VERSION 5.7 ;
  NOWIREEXTENSIONATPIN ON ;
  DIVIDERCHAR "/" ;
  BUSBITCHARS "[]" ;
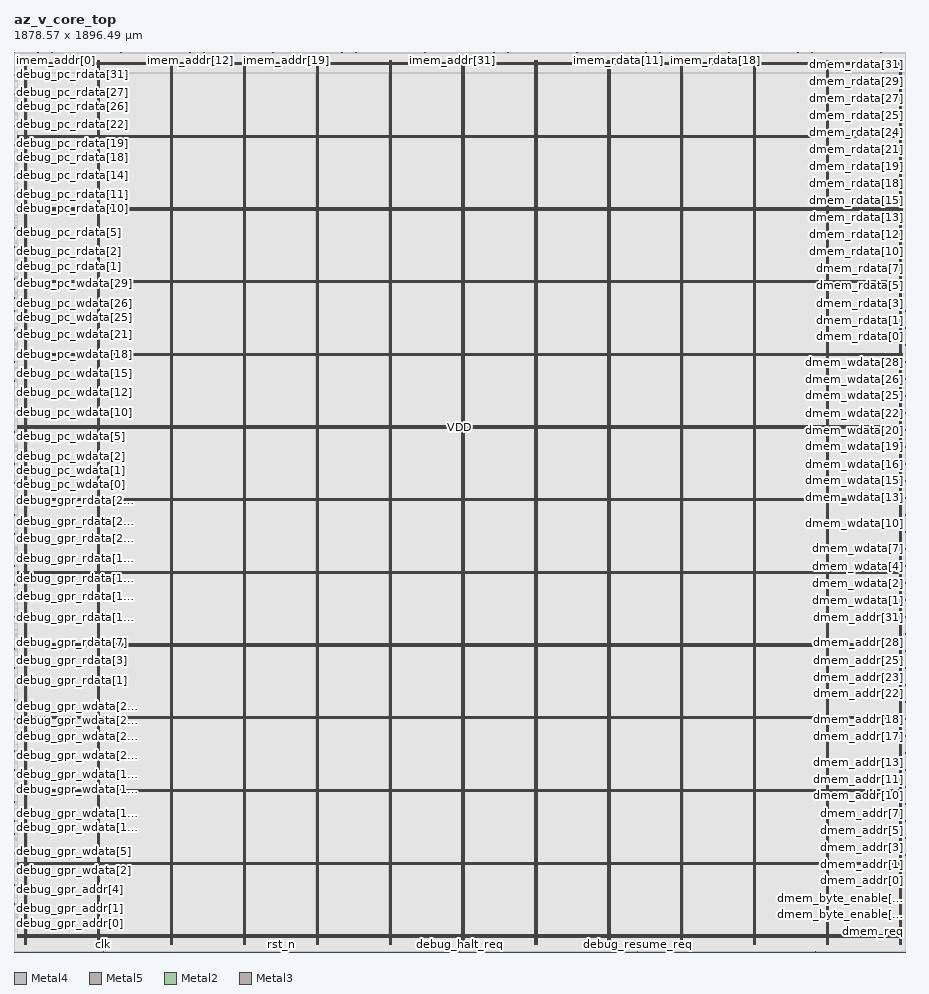
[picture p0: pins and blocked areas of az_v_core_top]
MACRO az_v_core_top
  CLASS BLOCK ;
  FOREIGN az_v_core_top ;
  ORIGIN 0.000 0.000 ;
  SIZE 1878.570 BY 1896.490 ;
  PIN VDD
    DIRECTION INOUT ;
    USE POWER ;
    PORT
      LAYER Metal4 ;
        RECT 22.240 15.380 23.840 1877.980 ;
    END
    PORT
      LAYER Metal4 ;
        RECT 175.840 15.380 177.440 1877.980 ;
    END
    PORT
      LAYER Metal4 ;
        RECT 329.440 15.380 331.040 1877.980 ;
    END
    PORT
      LAYER Metal4 ;
        RECT 483.040 15.380 484.640 1877.980 ;
    END
    PORT
      LAYER Metal4 ;
        RECT 636.640 15.380 638.240 1877.980 ;
    END
    PORT
      LAYER Metal4 ;
        RECT 790.240 15.380 791.840 1877.980 ;
    END
    PORT
      LAYER Metal4 ;
        RECT 943.840 15.380 945.440 1877.980 ;
    END
    PORT
      LAYER Metal4 ;
        RECT 1097.440 15.380 1099.040 1877.980 ;
    END
    PORT
      LAYER Metal4 ;
        RECT 1251.040 15.380 1252.640 1877.980 ;
    END
    PORT
      LAYER Metal4 ;
        RECT 1404.640 15.380 1406.240 1877.980 ;
    END
    PORT
      LAYER Metal4 ;
        RECT 1558.240 15.380 1559.840 1877.980 ;
    END
    PORT
      LAYER Metal4 ;
        RECT 1711.840 15.380 1713.440 1877.980 ;
    END
    PORT
      LAYER Metal4 ;
        RECT 1865.440 15.380 1867.040 1877.980 ;
    END
    PORT
      LAYER Metal5 ;
        RECT 6.720 31.530 1871.520 33.130 ;
    END
    PORT
      LAYER Metal5 ;
        RECT 6.720 184.710 1871.520 186.310 ;
    END
    PORT
      LAYER Metal5 ;
        RECT 6.720 337.890 1871.520 339.490 ;
    END
    PORT
      LAYER Metal5 ;
        RECT 6.720 491.070 1871.520 492.670 ;
    END
    PORT
      LAYER Metal5 ;
        RECT 6.720 644.250 1871.520 645.850 ;
    END
    PORT
      LAYER Metal5 ;
        RECT 6.720 797.430 1871.520 799.030 ;
    END
    PORT
      LAYER Metal5 ;
        RECT 6.720 950.610 1871.520 952.210 ;
    END
    PORT
      LAYER Metal5 ;
        RECT 6.720 1103.790 1871.520 1105.390 ;
    END
    PORT
      LAYER Metal5 ;
        RECT 6.720 1256.970 1871.520 1258.570 ;
    END
    PORT
      LAYER Metal5 ;
        RECT 6.720 1410.150 1871.520 1411.750 ;
    END
    PORT
      LAYER Metal5 ;
        RECT 6.720 1563.330 1871.520 1564.930 ;
    END
    PORT
      LAYER Metal5 ;
        RECT 6.720 1716.510 1871.520 1718.110 ;
    END
    PORT
      LAYER Metal5 ;
        RECT 6.720 1869.690 1871.520 1871.290 ;
    END
  END VDD
  PIN VSS
    DIRECTION INOUT ;
    USE GROUND ;
    PORT
      LAYER Metal4 ;
        RECT 25.540 15.380 27.140 1877.980 ;
    END
    PORT
      LAYER Metal4 ;
        RECT 179.140 15.380 180.740 1877.980 ;
    END
    PORT
      LAYER Metal4 ;
        RECT 332.740 15.380 334.340 1877.980 ;
    END
    PORT
      LAYER Metal4 ;
        RECT 486.340 15.380 487.940 1877.980 ;
    END
    PORT
      LAYER Metal4 ;
        RECT 639.940 15.380 641.540 1877.980 ;
    END
    PORT
      LAYER Metal4 ;
        RECT 793.540 15.380 795.140 1877.980 ;
    END
    PORT
      LAYER Metal4 ;
        RECT 947.140 15.380 948.740 1877.980 ;
    END
    PORT
      LAYER Metal4 ;
        RECT 1100.740 15.380 1102.340 1877.980 ;
    END
    PORT
      LAYER Metal4 ;
        RECT 1254.340 15.380 1255.940 1877.980 ;
    END
    PORT
      LAYER Metal4 ;
        RECT 1407.940 15.380 1409.540 1877.980 ;
    END
    PORT
      LAYER Metal4 ;
        RECT 1561.540 15.380 1563.140 1877.980 ;
    END
    PORT
      LAYER Metal4 ;
        RECT 1715.140 15.380 1716.740 1877.980 ;
    END
    PORT
      LAYER Metal4 ;
        RECT 1868.740 15.380 1870.340 1877.980 ;
    END
    PORT
      LAYER Metal5 ;
        RECT 6.720 34.830 1871.520 36.430 ;
    END
    PORT
      LAYER Metal5 ;
        RECT 6.720 188.010 1871.520 189.610 ;
    END
    PORT
      LAYER Metal5 ;
        RECT 6.720 341.190 1871.520 342.790 ;
    END
    PORT
      LAYER Metal5 ;
        RECT 6.720 494.370 1871.520 495.970 ;
    END
    PORT
      LAYER Metal5 ;
        RECT 6.720 647.550 1871.520 649.150 ;
    END
    PORT
      LAYER Metal5 ;
        RECT 6.720 800.730 1871.520 802.330 ;
    END
    PORT
      LAYER Metal5 ;
        RECT 6.720 953.910 1871.520 955.510 ;
    END
    PORT
      LAYER Metal5 ;
        RECT 6.720 1107.090 1871.520 1108.690 ;
    END
    PORT
      LAYER Metal5 ;
        RECT 6.720 1260.270 1871.520 1261.870 ;
    END
    PORT
      LAYER Metal5 ;
        RECT 6.720 1413.450 1871.520 1415.050 ;
    END
    PORT
      LAYER Metal5 ;
        RECT 6.720 1566.630 1871.520 1568.230 ;
    END
    PORT
      LAYER Metal5 ;
        RECT 6.720 1719.810 1871.520 1721.410 ;
    END
    PORT
      LAYER Metal5 ;
        RECT 6.720 1872.990 1871.520 1874.590 ;
    END
  END VSS
  PIN clk
    DIRECTION INPUT ;
    USE SIGNAL ;
    ANTENNAGATEAREA 4.738000 ;
    PORT
      LAYER Metal2 ;
        RECT 188.160 0.000 188.720 0.560 ;
    END
  END clk
  PIN debug_gpr_addr[0]
    DIRECTION INPUT ;
    USE SIGNAL ;
    ANTENNAGATEAREA 2.204000 ;
    PORT
      LAYER Metal3 ;
        RECT 0.000 60.480 0.560 61.040 ;
    END
  END debug_gpr_addr[0]
  PIN debug_gpr_addr[1]
    DIRECTION INPUT ;
    USE SIGNAL ;
    ANTENNAGATEAREA 2.204000 ;
    PORT
      LAYER Metal3 ;
        RECT 0.000 73.920 0.560 74.480 ;
    END
  END debug_gpr_addr[1]
  PIN debug_gpr_addr[2]
    DIRECTION INPUT ;
    USE SIGNAL ;
    ANTENNAGATEAREA 0.498500 ;
    PORT
      LAYER Metal3 ;
        RECT 0.000 87.360 0.560 87.920 ;
    END
  END debug_gpr_addr[2]
  PIN debug_gpr_addr[3]
    DIRECTION INPUT ;
    USE SIGNAL ;
    ANTENNAGATEAREA 1.102000 ;
    PORT
      LAYER Metal3 ;
        RECT 0.000 100.800 0.560 101.360 ;
    END
  END debug_gpr_addr[3]
  PIN debug_gpr_addr[4]
    DIRECTION INPUT ;
    USE SIGNAL ;
    ANTENNAGATEAREA 1.102000 ;
    PORT
      LAYER Metal3 ;
        RECT 0.000 114.240 0.560 114.800 ;
    END
  END debug_gpr_addr[4]
  PIN debug_gpr_rdata[0]
    DIRECTION OUTPUT ;
    USE SIGNAL ;
    ANTENNADIFFAREA 0.897600 ;
    PORT
      LAYER Metal3 ;
        RECT 0.000 557.760 0.560 558.320 ;
    END
  END debug_gpr_rdata[0]
  PIN debug_gpr_rdata[10]
    DIRECTION OUTPUT ;
    USE SIGNAL ;
    ANTENNADIFFAREA 0.897600 ;
    PORT
      LAYER Metal3 ;
        RECT 0.000 692.160 0.560 692.720 ;
    END
  END debug_gpr_rdata[10]
  PIN debug_gpr_rdata[11]
    DIRECTION OUTPUT ;
    USE SIGNAL ;
    ANTENNADIFFAREA 0.897600 ;
    PORT
      LAYER Metal3 ;
        RECT 0.000 705.600 0.560 706.160 ;
    END
  END debug_gpr_rdata[11]
  PIN debug_gpr_rdata[12]
    DIRECTION OUTPUT ;
    USE SIGNAL ;
    ANTENNADIFFAREA 0.897600 ;
    PORT
      LAYER Metal3 ;
        RECT 0.000 719.040 0.560 719.600 ;
    END
  END debug_gpr_rdata[12]
  PIN debug_gpr_rdata[13]
    DIRECTION OUTPUT ;
    USE SIGNAL ;
    ANTENNADIFFAREA 0.897600 ;
    PORT
      LAYER Metal3 ;
        RECT 0.000 732.480 0.560 733.040 ;
    END
  END debug_gpr_rdata[13]
  PIN debug_gpr_rdata[14]
    DIRECTION OUTPUT ;
    USE SIGNAL ;
    ANTENNADIFFAREA 0.897600 ;
    PORT
      LAYER Metal3 ;
        RECT 0.000 745.920 0.560 746.480 ;
    END
  END debug_gpr_rdata[14]
  PIN debug_gpr_rdata[15]
    DIRECTION OUTPUT ;
    USE SIGNAL ;
    ANTENNADIFFAREA 0.897600 ;
    PORT
      LAYER Metal3 ;
        RECT 0.000 759.360 0.560 759.920 ;
    END
  END debug_gpr_rdata[15]
  PIN debug_gpr_rdata[16]
    DIRECTION OUTPUT ;
    USE SIGNAL ;
    ANTENNADIFFAREA 0.897600 ;
    PORT
      LAYER Metal3 ;
        RECT 0.000 772.800 0.560 773.360 ;
    END
  END debug_gpr_rdata[16]
  PIN debug_gpr_rdata[17]
    DIRECTION OUTPUT ;
    USE SIGNAL ;
    ANTENNADIFFAREA 0.897600 ;
    PORT
      LAYER Metal3 ;
        RECT 0.000 786.240 0.560 786.800 ;
    END
  END debug_gpr_rdata[17]
  PIN debug_gpr_rdata[18]
    DIRECTION OUTPUT ;
    USE SIGNAL ;
    ANTENNADIFFAREA 0.897600 ;
    PORT
      LAYER Metal3 ;
        RECT 0.000 799.680 0.560 800.240 ;
    END
  END debug_gpr_rdata[18]
  PIN debug_gpr_rdata[19]
    DIRECTION OUTPUT ;
    USE SIGNAL ;
    ANTENNADIFFAREA 0.897600 ;
    PORT
      LAYER Metal3 ;
        RECT 0.000 813.120 0.560 813.680 ;
    END
  END debug_gpr_rdata[19]
  PIN debug_gpr_rdata[1]
    DIRECTION OUTPUT ;
    USE SIGNAL ;
    ANTENNADIFFAREA 0.897600 ;
    PORT
      LAYER Metal3 ;
        RECT 0.000 571.200 0.560 571.760 ;
    END
  END debug_gpr_rdata[1]
  PIN debug_gpr_rdata[20]
    DIRECTION OUTPUT ;
    USE SIGNAL ;
    ANTENNADIFFAREA 0.897600 ;
    PORT
      LAYER Metal3 ;
        RECT 0.000 826.560 0.560 827.120 ;
    END
  END debug_gpr_rdata[20]
  PIN debug_gpr_rdata[21]
    DIRECTION OUTPUT ;
    USE SIGNAL ;
    ANTENNADIFFAREA 0.897600 ;
    PORT
      LAYER Metal3 ;
        RECT 0.000 840.000 0.560 840.560 ;
    END
  END debug_gpr_rdata[21]
  PIN debug_gpr_rdata[22]
    DIRECTION OUTPUT ;
    USE SIGNAL ;
    ANTENNADIFFAREA 0.897600 ;
    PORT
      LAYER Metal3 ;
        RECT 0.000 853.440 0.560 854.000 ;
    END
  END debug_gpr_rdata[22]
  PIN debug_gpr_rdata[23]
    DIRECTION OUTPUT ;
    USE SIGNAL ;
    ANTENNADIFFAREA 0.897600 ;
    PORT
      LAYER Metal3 ;
        RECT 0.000 866.880 0.560 867.440 ;
    END
  END debug_gpr_rdata[23]
  PIN debug_gpr_rdata[24]
    DIRECTION OUTPUT ;
    USE SIGNAL ;
    ANTENNADIFFAREA 0.897600 ;
    PORT
      LAYER Metal3 ;
        RECT 0.000 880.320 0.560 880.880 ;
    END
  END debug_gpr_rdata[24]
  PIN debug_gpr_rdata[25]
    DIRECTION OUTPUT ;
    USE SIGNAL ;
    ANTENNADIFFAREA 0.897600 ;
    PORT
      LAYER Metal3 ;
        RECT 0.000 893.760 0.560 894.320 ;
    END
  END debug_gpr_rdata[25]
  PIN debug_gpr_rdata[26]
    DIRECTION OUTPUT ;
    USE SIGNAL ;
    ANTENNADIFFAREA 0.897600 ;
    PORT
      LAYER Metal3 ;
        RECT 0.000 907.200 0.560 907.760 ;
    END
  END debug_gpr_rdata[26]
  PIN debug_gpr_rdata[27]
    DIRECTION OUTPUT ;
    USE SIGNAL ;
    ANTENNADIFFAREA 0.897600 ;
    PORT
      LAYER Metal3 ;
        RECT 0.000 920.640 0.560 921.200 ;
    END
  END debug_gpr_rdata[27]
  PIN debug_gpr_rdata[28]
    DIRECTION OUTPUT ;
    USE SIGNAL ;
    ANTENNADIFFAREA 0.897600 ;
    PORT
      LAYER Metal3 ;
        RECT 0.000 934.080 0.560 934.640 ;
    END
  END debug_gpr_rdata[28]
  PIN debug_gpr_rdata[29]
    DIRECTION OUTPUT ;
    USE SIGNAL ;
    ANTENNADIFFAREA 0.897600 ;
    PORT
      LAYER Metal3 ;
        RECT 0.000 947.520 0.560 948.080 ;
    END
  END debug_gpr_rdata[29]
  PIN debug_gpr_rdata[2]
    DIRECTION OUTPUT ;
    USE SIGNAL ;
    ANTENNADIFFAREA 0.897600 ;
    PORT
      LAYER Metal3 ;
        RECT 0.000 584.640 0.560 585.200 ;
    END
  END debug_gpr_rdata[2]
  PIN debug_gpr_rdata[30]
    DIRECTION OUTPUT ;
    USE SIGNAL ;
    ANTENNADIFFAREA 0.897600 ;
    PORT
      LAYER Metal3 ;
        RECT 0.000 960.960 0.560 961.520 ;
    END
  END debug_gpr_rdata[30]
  PIN debug_gpr_rdata[31]
    DIRECTION OUTPUT ;
    USE SIGNAL ;
    ANTENNADIFFAREA 0.897600 ;
    PORT
      LAYER Metal3 ;
        RECT 0.000 974.400 0.560 974.960 ;
    END
  END debug_gpr_rdata[31]
  PIN debug_gpr_rdata[3]
    DIRECTION OUTPUT ;
    USE SIGNAL ;
    ANTENNADIFFAREA 0.897600 ;
    PORT
      LAYER Metal3 ;
        RECT 0.000 598.080 0.560 598.640 ;
    END
  END debug_gpr_rdata[3]
  PIN debug_gpr_rdata[4]
    DIRECTION OUTPUT ;
    USE SIGNAL ;
    ANTENNADIFFAREA 0.897600 ;
    PORT
      LAYER Metal3 ;
        RECT 0.000 611.520 0.560 612.080 ;
    END
  END debug_gpr_rdata[4]
  PIN debug_gpr_rdata[5]
    DIRECTION OUTPUT ;
    USE SIGNAL ;
    ANTENNADIFFAREA 0.897600 ;
    PORT
      LAYER Metal3 ;
        RECT 0.000 624.960 0.560 625.520 ;
    END
  END debug_gpr_rdata[5]
  PIN debug_gpr_rdata[6]
    DIRECTION OUTPUT ;
    USE SIGNAL ;
    ANTENNADIFFAREA 0.897600 ;
    PORT
      LAYER Metal3 ;
        RECT 0.000 638.400 0.560 638.960 ;
    END
  END debug_gpr_rdata[6]
  PIN debug_gpr_rdata[7]
    DIRECTION OUTPUT ;
    USE SIGNAL ;
    ANTENNADIFFAREA 0.897600 ;
    PORT
      LAYER Metal3 ;
        RECT 0.000 651.840 0.560 652.400 ;
    END
  END debug_gpr_rdata[7]
  PIN debug_gpr_rdata[8]
    DIRECTION OUTPUT ;
    USE SIGNAL ;
    ANTENNADIFFAREA 0.897600 ;
    PORT
      LAYER Metal3 ;
        RECT 0.000 665.280 0.560 665.840 ;
    END
  END debug_gpr_rdata[8]
  PIN debug_gpr_rdata[9]
    DIRECTION OUTPUT ;
    USE SIGNAL ;
    ANTENNADIFFAREA 0.897600 ;
    PORT
      LAYER Metal3 ;
        RECT 0.000 678.720 0.560 679.280 ;
    END
  END debug_gpr_rdata[9]
  PIN debug_gpr_wdata[0]
    DIRECTION INPUT ;
    USE SIGNAL ;
    ANTENNAGATEAREA 0.498500 ;
    PORT
      LAYER Metal3 ;
        RECT 0.000 127.680 0.560 128.240 ;
    END
  END debug_gpr_wdata[0]
  PIN debug_gpr_wdata[10]
    DIRECTION INPUT ;
    USE SIGNAL ;
    ANTENNAGATEAREA 1.102000 ;
    PORT
      LAYER Metal3 ;
        RECT 0.000 262.080 0.560 262.640 ;
    END
  END debug_gpr_wdata[10]
  PIN debug_gpr_wdata[11]
    DIRECTION INPUT ;
    USE SIGNAL ;
    ANTENNAGATEAREA 1.102000 ;
    PORT
      LAYER Metal3 ;
        RECT 0.000 275.520 0.560 276.080 ;
    END
  END debug_gpr_wdata[11]
  PIN debug_gpr_wdata[12]
    DIRECTION INPUT ;
    USE SIGNAL ;
    ANTENNAGATEAREA 0.498500 ;
    PORT
      LAYER Metal3 ;
        RECT 0.000 288.960 0.560 289.520 ;
    END
  END debug_gpr_wdata[12]
  PIN debug_gpr_wdata[13]
    DIRECTION INPUT ;
    USE SIGNAL ;
    ANTENNAGATEAREA 0.498500 ;
    PORT
      LAYER Metal3 ;
        RECT 0.000 302.400 0.560 302.960 ;
    END
  END debug_gpr_wdata[13]
  PIN debug_gpr_wdata[14]
    DIRECTION INPUT ;
    USE SIGNAL ;
    ANTENNAGATEAREA 0.498500 ;
    PORT
      LAYER Metal3 ;
        RECT 0.000 315.840 0.560 316.400 ;
    END
  END debug_gpr_wdata[14]
  PIN debug_gpr_wdata[15]
    DIRECTION INPUT ;
    USE SIGNAL ;
    ANTENNAGATEAREA 0.498500 ;
    PORT
      LAYER Metal3 ;
        RECT 0.000 329.280 0.560 329.840 ;
    END
  END debug_gpr_wdata[15]
  PIN debug_gpr_wdata[16]
    DIRECTION INPUT ;
    USE SIGNAL ;
    ANTENNAGATEAREA 0.498500 ;
    PORT
      LAYER Metal3 ;
        RECT 0.000 342.720 0.560 343.280 ;
    END
  END debug_gpr_wdata[16]
  PIN debug_gpr_wdata[17]
    DIRECTION INPUT ;
    USE SIGNAL ;
    ANTENNAGATEAREA 0.498500 ;
    PORT
      LAYER Metal3 ;
        RECT 0.000 356.160 0.560 356.720 ;
    END
  END debug_gpr_wdata[17]
  PIN debug_gpr_wdata[18]
    DIRECTION INPUT ;
    USE SIGNAL ;
    ANTENNAGATEAREA 0.498500 ;
    PORT
      LAYER Metal3 ;
        RECT 0.000 369.600 0.560 370.160 ;
    END
  END debug_gpr_wdata[18]
  PIN debug_gpr_wdata[19]
    DIRECTION INPUT ;
    USE SIGNAL ;
    ANTENNAGATEAREA 0.498500 ;
    PORT
      LAYER Metal3 ;
        RECT 0.000 383.040 0.560 383.600 ;
    END
  END debug_gpr_wdata[19]
  PIN debug_gpr_wdata[1]
    DIRECTION INPUT ;
    USE SIGNAL ;
    ANTENNAGATEAREA 1.102000 ;
    PORT
      LAYER Metal3 ;
        RECT 0.000 141.120 0.560 141.680 ;
    END
  END debug_gpr_wdata[1]
  PIN debug_gpr_wdata[20]
    DIRECTION INPUT ;
    USE SIGNAL ;
    ANTENNAGATEAREA 0.498500 ;
    PORT
      LAYER Metal3 ;
        RECT 0.000 396.480 0.560 397.040 ;
    END
  END debug_gpr_wdata[20]
  PIN debug_gpr_wdata[21]
    DIRECTION INPUT ;
    USE SIGNAL ;
    ANTENNAGATEAREA 0.498500 ;
    PORT
      LAYER Metal3 ;
        RECT 0.000 409.920 0.560 410.480 ;
    END
  END debug_gpr_wdata[21]
  PIN debug_gpr_wdata[22]
    DIRECTION INPUT ;
    USE SIGNAL ;
    ANTENNAGATEAREA 0.498500 ;
    PORT
      LAYER Metal3 ;
        RECT 0.000 423.360 0.560 423.920 ;
    END
  END debug_gpr_wdata[22]
  PIN debug_gpr_wdata[23]
    DIRECTION INPUT ;
    USE SIGNAL ;
    ANTENNAGATEAREA 0.498500 ;
    PORT
      LAYER Metal3 ;
        RECT 0.000 436.800 0.560 437.360 ;
    END
  END debug_gpr_wdata[23]
  PIN debug_gpr_wdata[24]
    DIRECTION INPUT ;
    USE SIGNAL ;
    ANTENNAGATEAREA 0.498500 ;
    PORT
      LAYER Metal3 ;
        RECT 0.000 450.240 0.560 450.800 ;
    END
  END debug_gpr_wdata[24]
  PIN debug_gpr_wdata[25]
    DIRECTION INPUT ;
    USE SIGNAL ;
    ANTENNAGATEAREA 0.498500 ;
    PORT
      LAYER Metal3 ;
        RECT 0.000 463.680 0.560 464.240 ;
    END
  END debug_gpr_wdata[25]
  PIN debug_gpr_wdata[26]
    DIRECTION INPUT ;
    USE SIGNAL ;
    ANTENNAGATEAREA 0.498500 ;
    PORT
      LAYER Metal3 ;
        RECT 0.000 477.120 0.560 477.680 ;
    END
  END debug_gpr_wdata[26]
  PIN debug_gpr_wdata[27]
    DIRECTION INPUT ;
    USE SIGNAL ;
    ANTENNAGATEAREA 0.498500 ;
    PORT
      LAYER Metal3 ;
        RECT 0.000 490.560 0.560 491.120 ;
    END
  END debug_gpr_wdata[27]
  PIN debug_gpr_wdata[28]
    DIRECTION INPUT ;
    USE SIGNAL ;
    ANTENNAGATEAREA 0.498500 ;
    PORT
      LAYER Metal3 ;
        RECT 0.000 504.000 0.560 504.560 ;
    END
  END debug_gpr_wdata[28]
  PIN debug_gpr_wdata[29]
    DIRECTION INPUT ;
    USE SIGNAL ;
    ANTENNAGATEAREA 0.498500 ;
    PORT
      LAYER Metal3 ;
        RECT 0.000 517.440 0.560 518.000 ;
    END
  END debug_gpr_wdata[29]
  PIN debug_gpr_wdata[2]
    DIRECTION INPUT ;
    USE SIGNAL ;
    ANTENNAGATEAREA 1.102000 ;
    PORT
      LAYER Metal3 ;
        RECT 0.000 154.560 0.560 155.120 ;
    END
  END debug_gpr_wdata[2]
  PIN debug_gpr_wdata[30]
    DIRECTION INPUT ;
    USE SIGNAL ;
    ANTENNAGATEAREA 0.498500 ;
    PORT
      LAYER Metal3 ;
        RECT 0.000 530.880 0.560 531.440 ;
    END
  END debug_gpr_wdata[30]
  PIN debug_gpr_wdata[31]
    DIRECTION INPUT ;
    USE SIGNAL ;
    ANTENNAGATEAREA 0.498500 ;
    PORT
      LAYER Metal3 ;
        RECT 0.000 544.320 0.560 544.880 ;
    END
  END debug_gpr_wdata[31]
  PIN debug_gpr_wdata[3]
    DIRECTION INPUT ;
    USE SIGNAL ;
    ANTENNAGATEAREA 1.102000 ;
    PORT
      LAYER Metal3 ;
        RECT 0.000 168.000 0.560 168.560 ;
    END
  END debug_gpr_wdata[3]
  PIN debug_gpr_wdata[4]
    DIRECTION INPUT ;
    USE SIGNAL ;
    ANTENNAGATEAREA 1.102000 ;
    PORT
      LAYER Metal3 ;
        RECT 0.000 181.440 0.560 182.000 ;
    END
  END debug_gpr_wdata[4]
  PIN debug_gpr_wdata[5]
    DIRECTION INPUT ;
    USE SIGNAL ;
    ANTENNAGATEAREA 1.102000 ;
    PORT
      LAYER Metal3 ;
        RECT 0.000 194.880 0.560 195.440 ;
    END
  END debug_gpr_wdata[5]
  PIN debug_gpr_wdata[6]
    DIRECTION INPUT ;
    USE SIGNAL ;
    ANTENNAGATEAREA 0.498500 ;
    PORT
      LAYER Metal3 ;
        RECT 0.000 208.320 0.560 208.880 ;
    END
  END debug_gpr_wdata[6]
  PIN debug_gpr_wdata[7]
    DIRECTION INPUT ;
    USE SIGNAL ;
    ANTENNAGATEAREA 0.498500 ;
    PORT
      LAYER Metal3 ;
        RECT 0.000 221.760 0.560 222.320 ;
    END
  END debug_gpr_wdata[7]
  PIN debug_gpr_wdata[8]
    DIRECTION INPUT ;
    USE SIGNAL ;
    ANTENNAGATEAREA 0.498500 ;
    PORT
      LAYER Metal3 ;
        RECT 0.000 235.200 0.560 235.760 ;
    END
  END debug_gpr_wdata[8]
  PIN debug_gpr_wdata[9]
    DIRECTION INPUT ;
    USE SIGNAL ;
    ANTENNAGATEAREA 1.102000 ;
    PORT
      LAYER Metal3 ;
        RECT 0.000 248.640 0.560 249.200 ;
    END
  END debug_gpr_wdata[9]
  PIN debug_gpr_wen
    DIRECTION INPUT ;
    USE SIGNAL ;
    ANTENNAGATEAREA 0.498500 ;
    PORT
      LAYER Metal3 ;
        RECT 0.000 47.040 0.560 47.600 ;
    END
  END debug_gpr_wen
  PIN debug_halt_req
    DIRECTION INPUT ;
    USE SIGNAL ;
    ANTENNAGATEAREA 0.498500 ;
    PORT
      LAYER Metal2 ;
        RECT 938.560 0.000 939.120 0.560 ;
    END
  END debug_halt_req
  PIN debug_halted
    DIRECTION OUTPUT ;
    USE SIGNAL ;
    ANTENNADIFFAREA 0.897600 ;
    PORT
      LAYER Metal2 ;
        RECT 1688.960 0.000 1689.520 0.560 ;
    END
  END debug_halted
  PIN debug_pc_rdata[0]
    DIRECTION OUTPUT ;
    USE SIGNAL ;
    ANTENNADIFFAREA 0.897600 ;
    PORT
      LAYER Metal3 ;
        RECT 0.000 1431.360 0.560 1431.920 ;
    END
  END debug_pc_rdata[0]
  PIN debug_pc_rdata[10]
    DIRECTION OUTPUT ;
    USE SIGNAL ;
    ANTENNADIFFAREA 0.897600 ;
    PORT
      LAYER Metal3 ;
        RECT 0.000 1565.760 0.560 1566.320 ;
    END
  END debug_pc_rdata[10]
  PIN debug_pc_rdata[11]
    DIRECTION OUTPUT ;
    USE SIGNAL ;
    ANTENNADIFFAREA 0.897600 ;
    PORT
      LAYER Metal3 ;
        RECT 0.000 1579.200 0.560 1579.760 ;
    END
  END debug_pc_rdata[11]
  PIN debug_pc_rdata[12]
    DIRECTION OUTPUT ;
    USE SIGNAL ;
    ANTENNADIFFAREA 0.897600 ;
    PORT
      LAYER Metal3 ;
        RECT 0.000 1592.640 0.560 1593.200 ;
    END
  END debug_pc_rdata[12]
  PIN debug_pc_rdata[13]
    DIRECTION OUTPUT ;
    USE SIGNAL ;
    ANTENNADIFFAREA 0.897600 ;
    PORT
      LAYER Metal3 ;
        RECT 0.000 1606.080 0.560 1606.640 ;
    END
  END debug_pc_rdata[13]
  PIN debug_pc_rdata[14]
    DIRECTION OUTPUT ;
    USE SIGNAL ;
    ANTENNADIFFAREA 0.897600 ;
    PORT
      LAYER Metal3 ;
        RECT 0.000 1619.520 0.560 1620.080 ;
    END
  END debug_pc_rdata[14]
  PIN debug_pc_rdata[15]
    DIRECTION OUTPUT ;
    USE SIGNAL ;
    ANTENNADIFFAREA 0.897600 ;
    PORT
      LAYER Metal3 ;
        RECT 0.000 1632.960 0.560 1633.520 ;
    END
  END debug_pc_rdata[15]
  PIN debug_pc_rdata[16]
    DIRECTION OUTPUT ;
    USE SIGNAL ;
    ANTENNADIFFAREA 0.897600 ;
    PORT
      LAYER Metal3 ;
        RECT 0.000 1646.400 0.560 1646.960 ;
    END
  END debug_pc_rdata[16]
  PIN debug_pc_rdata[17]
    DIRECTION OUTPUT ;
    USE SIGNAL ;
    ANTENNADIFFAREA 0.897600 ;
    PORT
      LAYER Metal3 ;
        RECT 0.000 1659.840 0.560 1660.400 ;
    END
  END debug_pc_rdata[17]
  PIN debug_pc_rdata[18]
    DIRECTION OUTPUT ;
    USE SIGNAL ;
    ANTENNADIFFAREA 0.897600 ;
    PORT
      LAYER Metal3 ;
        RECT 0.000 1673.280 0.560 1673.840 ;
    END
  END debug_pc_rdata[18]
  PIN debug_pc_rdata[19]
    DIRECTION OUTPUT ;
    USE SIGNAL ;
    ANTENNADIFFAREA 0.897600 ;
    PORT
      LAYER Metal3 ;
        RECT 0.000 1686.720 0.560 1687.280 ;
    END
  END debug_pc_rdata[19]
  PIN debug_pc_rdata[1]
    DIRECTION OUTPUT ;
    USE SIGNAL ;
    ANTENNADIFFAREA 0.897600 ;
    PORT
      LAYER Metal3 ;
        RECT 0.000 1444.800 0.560 1445.360 ;
    END
  END debug_pc_rdata[1]
  PIN debug_pc_rdata[20]
    DIRECTION OUTPUT ;
    USE SIGNAL ;
    ANTENNADIFFAREA 0.897600 ;
    PORT
      LAYER Metal3 ;
        RECT 0.000 1700.160 0.560 1700.720 ;
    END
  END debug_pc_rdata[20]
  PIN debug_pc_rdata[21]
    DIRECTION OUTPUT ;
    USE SIGNAL ;
    ANTENNADIFFAREA 0.897600 ;
    PORT
      LAYER Metal3 ;
        RECT 0.000 1713.600 0.560 1714.160 ;
    END
  END debug_pc_rdata[21]
  PIN debug_pc_rdata[22]
    DIRECTION OUTPUT ;
    USE SIGNAL ;
    ANTENNADIFFAREA 0.897600 ;
    PORT
      LAYER Metal3 ;
        RECT 0.000 1727.040 0.560 1727.600 ;
    END
  END debug_pc_rdata[22]
  PIN debug_pc_rdata[23]
    DIRECTION OUTPUT ;
    USE SIGNAL ;
    ANTENNADIFFAREA 0.897600 ;
    PORT
      LAYER Metal3 ;
        RECT 0.000 1740.480 0.560 1741.040 ;
    END
  END debug_pc_rdata[23]
  PIN debug_pc_rdata[24]
    DIRECTION OUTPUT ;
    USE SIGNAL ;
    ANTENNADIFFAREA 0.897600 ;
    PORT
      LAYER Metal3 ;
        RECT 0.000 1753.920 0.560 1754.480 ;
    END
  END debug_pc_rdata[24]
  PIN debug_pc_rdata[25]
    DIRECTION OUTPUT ;
    USE SIGNAL ;
    ANTENNADIFFAREA 0.897600 ;
    PORT
      LAYER Metal3 ;
        RECT 0.000 1767.360 0.560 1767.920 ;
    END
  END debug_pc_rdata[25]
  PIN debug_pc_rdata[26]
    DIRECTION OUTPUT ;
    USE SIGNAL ;
    ANTENNADIFFAREA 0.897600 ;
    PORT
      LAYER Metal3 ;
        RECT 0.000 1780.800 0.560 1781.360 ;
    END
  END debug_pc_rdata[26]
  PIN debug_pc_rdata[27]
    DIRECTION OUTPUT ;
    USE SIGNAL ;
    ANTENNADIFFAREA 0.897600 ;
    PORT
      LAYER Metal3 ;
        RECT 0.000 1794.240 0.560 1794.800 ;
    END
  END debug_pc_rdata[27]
  PIN debug_pc_rdata[28]
    DIRECTION OUTPUT ;
    USE SIGNAL ;
    ANTENNADIFFAREA 0.897600 ;
    PORT
      LAYER Metal3 ;
        RECT 0.000 1807.680 0.560 1808.240 ;
    END
  END debug_pc_rdata[28]
  PIN debug_pc_rdata[29]
    DIRECTION OUTPUT ;
    USE SIGNAL ;
    ANTENNADIFFAREA 0.897600 ;
    PORT
      LAYER Metal3 ;
        RECT 0.000 1821.120 0.560 1821.680 ;
    END
  END debug_pc_rdata[29]
  PIN debug_pc_rdata[2]
    DIRECTION OUTPUT ;
    USE SIGNAL ;
    ANTENNADIFFAREA 0.897600 ;
    PORT
      LAYER Metal3 ;
        RECT 0.000 1458.240 0.560 1458.800 ;
    END
  END debug_pc_rdata[2]
  PIN debug_pc_rdata[30]
    DIRECTION OUTPUT ;
    USE SIGNAL ;
    ANTENNADIFFAREA 0.897600 ;
    PORT
      LAYER Metal3 ;
        RECT 0.000 1834.560 0.560 1835.120 ;
    END
  END debug_pc_rdata[30]
  PIN debug_pc_rdata[31]
    DIRECTION OUTPUT ;
    USE SIGNAL ;
    ANTENNADIFFAREA 0.897600 ;
    PORT
      LAYER Metal3 ;
        RECT 0.000 1848.000 0.560 1848.560 ;
    END
  END debug_pc_rdata[31]
  PIN debug_pc_rdata[3]
    DIRECTION OUTPUT ;
    USE SIGNAL ;
    ANTENNADIFFAREA 0.897600 ;
    PORT
      LAYER Metal3 ;
        RECT 0.000 1471.680 0.560 1472.240 ;
    END
  END debug_pc_rdata[3]
  PIN debug_pc_rdata[4]
    DIRECTION OUTPUT ;
    USE SIGNAL ;
    ANTENNADIFFAREA 0.897600 ;
    PORT
      LAYER Metal3 ;
        RECT 0.000 1485.120 0.560 1485.680 ;
    END
  END debug_pc_rdata[4]
  PIN debug_pc_rdata[5]
    DIRECTION OUTPUT ;
    USE SIGNAL ;
    ANTENNADIFFAREA 0.897600 ;
    PORT
      LAYER Metal3 ;
        RECT 0.000 1498.560 0.560 1499.120 ;
    END
  END debug_pc_rdata[5]
  PIN debug_pc_rdata[6]
    DIRECTION OUTPUT ;
    USE SIGNAL ;
    ANTENNADIFFAREA 0.897600 ;
    PORT
      LAYER Metal3 ;
        RECT 0.000 1512.000 0.560 1512.560 ;
    END
  END debug_pc_rdata[6]
  PIN debug_pc_rdata[7]
    DIRECTION OUTPUT ;
    USE SIGNAL ;
    ANTENNADIFFAREA 0.897600 ;
    PORT
      LAYER Metal3 ;
        RECT 0.000 1525.440 0.560 1526.000 ;
    END
  END debug_pc_rdata[7]
  PIN debug_pc_rdata[8]
    DIRECTION OUTPUT ;
    USE SIGNAL ;
    ANTENNADIFFAREA 0.897600 ;
    PORT
      LAYER Metal3 ;
        RECT 0.000 1538.880 0.560 1539.440 ;
    END
  END debug_pc_rdata[8]
  PIN debug_pc_rdata[9]
    DIRECTION OUTPUT ;
    USE SIGNAL ;
    ANTENNADIFFAREA 0.897600 ;
    PORT
      LAYER Metal3 ;
        RECT 0.000 1552.320 0.560 1552.880 ;
    END
  END debug_pc_rdata[9]
  PIN debug_pc_wdata[0]
    DIRECTION INPUT ;
    USE SIGNAL ;
    ANTENNAGATEAREA 0.498500 ;
    PORT
      LAYER Metal3 ;
        RECT 0.000 1001.280 0.560 1001.840 ;
    END
  END debug_pc_wdata[0]
  PIN debug_pc_wdata[10]
    DIRECTION INPUT ;
    USE SIGNAL ;
    ANTENNAGATEAREA 0.498500 ;
    PORT
      LAYER Metal3 ;
        RECT 0.000 1135.680 0.560 1136.240 ;
    END
  END debug_pc_wdata[10]
  PIN debug_pc_wdata[11]
    DIRECTION INPUT ;
    USE SIGNAL ;
    ANTENNAGATEAREA 0.498500 ;
    PORT
      LAYER Metal3 ;
        RECT 0.000 1149.120 0.560 1149.680 ;
    END
  END debug_pc_wdata[11]
  PIN debug_pc_wdata[12]
    DIRECTION INPUT ;
    USE SIGNAL ;
    ANTENNAGATEAREA 0.498500 ;
    PORT
      LAYER Metal3 ;
        RECT 0.000 1162.560 0.560 1163.120 ;
    END
  END debug_pc_wdata[12]
  PIN debug_pc_wdata[13]
    DIRECTION INPUT ;
    USE SIGNAL ;
    ANTENNAGATEAREA 0.498500 ;
    PORT
      LAYER Metal3 ;
        RECT 0.000 1176.000 0.560 1176.560 ;
    END
  END debug_pc_wdata[13]
  PIN debug_pc_wdata[14]
    DIRECTION INPUT ;
    USE SIGNAL ;
    ANTENNAGATEAREA 0.498500 ;
    PORT
      LAYER Metal3 ;
        RECT 0.000 1189.440 0.560 1190.000 ;
    END
  END debug_pc_wdata[14]
  PIN debug_pc_wdata[15]
    DIRECTION INPUT ;
    USE SIGNAL ;
    ANTENNAGATEAREA 0.498500 ;
    PORT
      LAYER Metal3 ;
        RECT 0.000 1202.880 0.560 1203.440 ;
    END
  END debug_pc_wdata[15]
  PIN debug_pc_wdata[16]
    DIRECTION INPUT ;
    USE SIGNAL ;
    ANTENNAGATEAREA 0.498500 ;
    PORT
      LAYER Metal3 ;
        RECT 0.000 1216.320 0.560 1216.880 ;
    END
  END debug_pc_wdata[16]
  PIN debug_pc_wdata[17]
    DIRECTION INPUT ;
    USE SIGNAL ;
    ANTENNAGATEAREA 0.498500 ;
    PORT
      LAYER Metal3 ;
        RECT 0.000 1229.760 0.560 1230.320 ;
    END
  END debug_pc_wdata[17]
  PIN debug_pc_wdata[18]
    DIRECTION INPUT ;
    USE SIGNAL ;
    ANTENNAGATEAREA 0.498500 ;
    PORT
      LAYER Metal3 ;
        RECT 0.000 1243.200 0.560 1243.760 ;
    END
  END debug_pc_wdata[18]
  PIN debug_pc_wdata[19]
    DIRECTION INPUT ;
    USE SIGNAL ;
    ANTENNAGATEAREA 0.498500 ;
    PORT
      LAYER Metal3 ;
        RECT 0.000 1256.640 0.560 1257.200 ;
    END
  END debug_pc_wdata[19]
  PIN debug_pc_wdata[1]
    DIRECTION INPUT ;
    USE SIGNAL ;
    ANTENNAGATEAREA 0.498500 ;
    PORT
      LAYER Metal3 ;
        RECT 0.000 1014.720 0.560 1015.280 ;
    END
  END debug_pc_wdata[1]
  PIN debug_pc_wdata[20]
    DIRECTION INPUT ;
    USE SIGNAL ;
    ANTENNAGATEAREA 0.498500 ;
    PORT
      LAYER Metal3 ;
        RECT 0.000 1270.080 0.560 1270.640 ;
    END
  END debug_pc_wdata[20]
  PIN debug_pc_wdata[21]
    DIRECTION INPUT ;
    USE SIGNAL ;
    ANTENNAGATEAREA 0.498500 ;
    PORT
      LAYER Metal3 ;
        RECT 0.000 1283.520 0.560 1284.080 ;
    END
  END debug_pc_wdata[21]
  PIN debug_pc_wdata[22]
    DIRECTION INPUT ;
    USE SIGNAL ;
    ANTENNAGATEAREA 0.498500 ;
    PORT
      LAYER Metal3 ;
        RECT 0.000 1296.960 0.560 1297.520 ;
    END
  END debug_pc_wdata[22]
  PIN debug_pc_wdata[23]
    DIRECTION INPUT ;
    USE SIGNAL ;
    ANTENNAGATEAREA 0.498500 ;
    PORT
      LAYER Metal3 ;
        RECT 0.000 1310.400 0.560 1310.960 ;
    END
  END debug_pc_wdata[23]
  PIN debug_pc_wdata[24]
    DIRECTION INPUT ;
    USE SIGNAL ;
    ANTENNAGATEAREA 0.498500 ;
    PORT
      LAYER Metal3 ;
        RECT 0.000 1323.840 0.560 1324.400 ;
    END
  END debug_pc_wdata[24]
  PIN debug_pc_wdata[25]
    DIRECTION INPUT ;
    USE SIGNAL ;
    ANTENNAGATEAREA 0.498500 ;
    PORT
      LAYER Metal3 ;
        RECT 0.000 1337.280 0.560 1337.840 ;
    END
  END debug_pc_wdata[25]
  PIN debug_pc_wdata[26]
    DIRECTION INPUT ;
    USE SIGNAL ;
    ANTENNAGATEAREA 0.498500 ;
    PORT
      LAYER Metal3 ;
        RECT 0.000 1350.720 0.560 1351.280 ;
    END
  END debug_pc_wdata[26]
  PIN debug_pc_wdata[27]
    DIRECTION INPUT ;
    USE SIGNAL ;
    ANTENNAGATEAREA 0.498500 ;
    PORT
      LAYER Metal3 ;
        RECT 0.000 1364.160 0.560 1364.720 ;
    END
  END debug_pc_wdata[27]
  PIN debug_pc_wdata[28]
    DIRECTION INPUT ;
    USE SIGNAL ;
    ANTENNAGATEAREA 0.498500 ;
    PORT
      LAYER Metal3 ;
        RECT 0.000 1377.600 0.560 1378.160 ;
    END
  END debug_pc_wdata[28]
  PIN debug_pc_wdata[29]
    DIRECTION INPUT ;
    USE SIGNAL ;
    ANTENNAGATEAREA 0.498500 ;
    PORT
      LAYER Metal3 ;
        RECT 0.000 1391.040 0.560 1391.600 ;
    END
  END debug_pc_wdata[29]
  PIN debug_pc_wdata[2]
    DIRECTION INPUT ;
    USE SIGNAL ;
    ANTENNAGATEAREA 0.498500 ;
    PORT
      LAYER Metal3 ;
        RECT 0.000 1028.160 0.560 1028.720 ;
    END
  END debug_pc_wdata[2]
  PIN debug_pc_wdata[30]
    DIRECTION INPUT ;
    USE SIGNAL ;
    ANTENNAGATEAREA 0.498500 ;
    PORT
      LAYER Metal3 ;
        RECT 0.000 1404.480 0.560 1405.040 ;
    END
  END debug_pc_wdata[30]
  PIN debug_pc_wdata[31]
    DIRECTION INPUT ;
    USE SIGNAL ;
    ANTENNAGATEAREA 0.498500 ;
    PORT
      LAYER Metal3 ;
        RECT 0.000 1417.920 0.560 1418.480 ;
    END
  END debug_pc_wdata[31]
  PIN debug_pc_wdata[3]
    DIRECTION INPUT ;
    USE SIGNAL ;
    ANTENNAGATEAREA 0.498500 ;
    PORT
      LAYER Metal3 ;
        RECT 0.000 1041.600 0.560 1042.160 ;
    END
  END debug_pc_wdata[3]
  PIN debug_pc_wdata[4]
    DIRECTION INPUT ;
    USE SIGNAL ;
    ANTENNAGATEAREA 0.498500 ;
    PORT
      LAYER Metal3 ;
        RECT 0.000 1055.040 0.560 1055.600 ;
    END
  END debug_pc_wdata[4]
  PIN debug_pc_wdata[5]
    DIRECTION INPUT ;
    USE SIGNAL ;
    ANTENNAGATEAREA 0.498500 ;
    PORT
      LAYER Metal3 ;
        RECT 0.000 1068.480 0.560 1069.040 ;
    END
  END debug_pc_wdata[5]
  PIN debug_pc_wdata[6]
    DIRECTION INPUT ;
    USE SIGNAL ;
    ANTENNAGATEAREA 0.498500 ;
    PORT
      LAYER Metal3 ;
        RECT 0.000 1081.920 0.560 1082.480 ;
    END
  END debug_pc_wdata[6]
  PIN debug_pc_wdata[7]
    DIRECTION INPUT ;
    USE SIGNAL ;
    ANTENNAGATEAREA 0.498500 ;
    PORT
      LAYER Metal3 ;
        RECT 0.000 1095.360 0.560 1095.920 ;
    END
  END debug_pc_wdata[7]
  PIN debug_pc_wdata[8]
    DIRECTION INPUT ;
    USE SIGNAL ;
    ANTENNAGATEAREA 0.498500 ;
    PORT
      LAYER Metal3 ;
        RECT 0.000 1108.800 0.560 1109.360 ;
    END
  END debug_pc_wdata[8]
  PIN debug_pc_wdata[9]
    DIRECTION INPUT ;
    USE SIGNAL ;
    ANTENNAGATEAREA 0.498500 ;
    PORT
      LAYER Metal3 ;
        RECT 0.000 1122.240 0.560 1122.800 ;
    END
  END debug_pc_wdata[9]
  PIN debug_pc_wen
    DIRECTION INPUT ;
    USE SIGNAL ;
    ANTENNAGATEAREA 0.498500 ;
    PORT
      LAYER Metal3 ;
        RECT 0.000 987.840 0.560 988.400 ;
    END
  END debug_pc_wen
  PIN debug_resume_req
    DIRECTION INPUT ;
    USE SIGNAL ;
    ANTENNAGATEAREA 0.498500 ;
    PORT
      LAYER Metal2 ;
        RECT 1313.760 0.000 1314.320 0.560 ;
    END
  END debug_resume_req
  PIN dmem_addr[0]
    DIRECTION OUTPUT ;
    USE SIGNAL ;
    ANTENNADIFFAREA 0.360800 ;
    PORT
      LAYER Metal3 ;
        RECT 1878.010 150.080 1878.570 150.640 ;
    END
  END dmem_addr[0]
  PIN dmem_addr[10]
    DIRECTION OUTPUT ;
    USE SIGNAL ;
    ANTENNADIFFAREA 0.897600 ;
    PORT
      LAYER Metal3 ;
        RECT 1878.010 329.280 1878.570 329.840 ;
    END
  END dmem_addr[10]
  PIN dmem_addr[11]
    DIRECTION OUTPUT ;
    USE SIGNAL ;
    ANTENNADIFFAREA 0.897600 ;
    PORT
      LAYER Metal3 ;
        RECT 1878.010 347.200 1878.570 347.760 ;
    END
  END dmem_addr[11]
  PIN dmem_addr[12]
    DIRECTION OUTPUT ;
    USE SIGNAL ;
    ANTENNADIFFAREA 0.897600 ;
    PORT
      LAYER Metal3 ;
        RECT 1878.010 365.120 1878.570 365.680 ;
    END
  END dmem_addr[12]
  PIN dmem_addr[13]
    DIRECTION OUTPUT ;
    USE SIGNAL ;
    ANTENNADIFFAREA 0.897600 ;
    PORT
      LAYER Metal3 ;
        RECT 1878.010 383.040 1878.570 383.600 ;
    END
  END dmem_addr[13]
  PIN dmem_addr[14]
    DIRECTION OUTPUT ;
    USE SIGNAL ;
    ANTENNADIFFAREA 0.897600 ;
    PORT
      LAYER Metal3 ;
        RECT 1878.010 400.960 1878.570 401.520 ;
    END
  END dmem_addr[14]
  PIN dmem_addr[15]
    DIRECTION OUTPUT ;
    USE SIGNAL ;
    ANTENNADIFFAREA 0.897600 ;
    PORT
      LAYER Metal3 ;
        RECT 1878.010 418.880 1878.570 419.440 ;
    END
  END dmem_addr[15]
  PIN dmem_addr[16]
    DIRECTION OUTPUT ;
    USE SIGNAL ;
    ANTENNADIFFAREA 0.897600 ;
    PORT
      LAYER Metal3 ;
        RECT 1878.010 436.800 1878.570 437.360 ;
    END
  END dmem_addr[16]
  PIN dmem_addr[17]
    DIRECTION OUTPUT ;
    USE SIGNAL ;
    ANTENNADIFFAREA 0.897600 ;
    PORT
      LAYER Metal3 ;
        RECT 1878.010 454.720 1878.570 455.280 ;
    END
  END dmem_addr[17]
  PIN dmem_addr[18]
    DIRECTION OUTPUT ;
    USE SIGNAL ;
    ANTENNADIFFAREA 0.897600 ;
    PORT
      LAYER Metal3 ;
        RECT 1878.010 472.640 1878.570 473.200 ;
    END
  END dmem_addr[18]
  PIN dmem_addr[19]
    DIRECTION OUTPUT ;
    USE SIGNAL ;
    ANTENNADIFFAREA 0.897600 ;
    PORT
      LAYER Metal3 ;
        RECT 1878.010 490.560 1878.570 491.120 ;
    END
  END dmem_addr[19]
  PIN dmem_addr[1]
    DIRECTION OUTPUT ;
    USE SIGNAL ;
    ANTENNADIFFAREA 0.360800 ;
    PORT
      LAYER Metal3 ;
        RECT 1878.010 168.000 1878.570 168.560 ;
    END
  END dmem_addr[1]
  PIN dmem_addr[20]
    DIRECTION OUTPUT ;
    USE SIGNAL ;
    ANTENNADIFFAREA 0.897600 ;
    PORT
      LAYER Metal3 ;
        RECT 1878.010 508.480 1878.570 509.040 ;
    END
  END dmem_addr[20]
  PIN dmem_addr[21]
    DIRECTION OUTPUT ;
    USE SIGNAL ;
    ANTENNADIFFAREA 0.897600 ;
    PORT
      LAYER Metal3 ;
        RECT 1878.010 526.400 1878.570 526.960 ;
    END
  END dmem_addr[21]
  PIN dmem_addr[22]
    DIRECTION OUTPUT ;
    USE SIGNAL ;
    ANTENNADIFFAREA 0.897600 ;
    PORT
      LAYER Metal3 ;
        RECT 1878.010 544.320 1878.570 544.880 ;
    END
  END dmem_addr[22]
  PIN dmem_addr[23]
    DIRECTION OUTPUT ;
    USE SIGNAL ;
    ANTENNADIFFAREA 0.897600 ;
    PORT
      LAYER Metal3 ;
        RECT 1878.010 562.240 1878.570 562.800 ;
    END
  END dmem_addr[23]
  PIN dmem_addr[24]
    DIRECTION OUTPUT ;
    USE SIGNAL ;
    ANTENNADIFFAREA 0.897600 ;
    PORT
      LAYER Metal3 ;
        RECT 1878.010 580.160 1878.570 580.720 ;
    END
  END dmem_addr[24]
  PIN dmem_addr[25]
    DIRECTION OUTPUT ;
    USE SIGNAL ;
    ANTENNADIFFAREA 0.897600 ;
    PORT
      LAYER Metal3 ;
        RECT 1878.010 598.080 1878.570 598.640 ;
    END
  END dmem_addr[25]
  PIN dmem_addr[26]
    DIRECTION OUTPUT ;
    USE SIGNAL ;
    ANTENNADIFFAREA 0.897600 ;
    PORT
      LAYER Metal3 ;
        RECT 1878.010 616.000 1878.570 616.560 ;
    END
  END dmem_addr[26]
  PIN dmem_addr[27]
    DIRECTION OUTPUT ;
    USE SIGNAL ;
    ANTENNADIFFAREA 0.897600 ;
    PORT
      LAYER Metal3 ;
        RECT 1878.010 633.920 1878.570 634.480 ;
    END
  END dmem_addr[27]
  PIN dmem_addr[28]
    DIRECTION OUTPUT ;
    USE SIGNAL ;
    ANTENNADIFFAREA 0.897600 ;
    PORT
      LAYER Metal3 ;
        RECT 1878.010 651.840 1878.570 652.400 ;
    END
  END dmem_addr[28]
  PIN dmem_addr[29]
    DIRECTION OUTPUT ;
    USE SIGNAL ;
    ANTENNADIFFAREA 0.897600 ;
    PORT
      LAYER Metal3 ;
        RECT 1878.010 669.760 1878.570 670.320 ;
    END
  END dmem_addr[29]
  PIN dmem_addr[2]
    DIRECTION OUTPUT ;
    USE SIGNAL ;
    ANTENNADIFFAREA 0.897600 ;
    PORT
      LAYER Metal3 ;
        RECT 1878.010 185.920 1878.570 186.480 ;
    END
  END dmem_addr[2]
  PIN dmem_addr[30]
    DIRECTION OUTPUT ;
    USE SIGNAL ;
    ANTENNADIFFAREA 0.897600 ;
    PORT
      LAYER Metal3 ;
        RECT 1878.010 687.680 1878.570 688.240 ;
    END
  END dmem_addr[30]
  PIN dmem_addr[31]
    DIRECTION OUTPUT ;
    USE SIGNAL ;
    ANTENNADIFFAREA 0.897600 ;
    PORT
      LAYER Metal3 ;
        RECT 1878.010 705.600 1878.570 706.160 ;
    END
  END dmem_addr[31]
  PIN dmem_addr[3]
    DIRECTION OUTPUT ;
    USE SIGNAL ;
    ANTENNADIFFAREA 0.897600 ;
    PORT
      LAYER Metal3 ;
        RECT 1878.010 203.840 1878.570 204.400 ;
    END
  END dmem_addr[3]
  PIN dmem_addr[4]
    DIRECTION OUTPUT ;
    USE SIGNAL ;
    ANTENNADIFFAREA 0.897600 ;
    PORT
      LAYER Metal3 ;
        RECT 1878.010 221.760 1878.570 222.320 ;
    END
  END dmem_addr[4]
  PIN dmem_addr[5]
    DIRECTION OUTPUT ;
    USE SIGNAL ;
    ANTENNADIFFAREA 0.897600 ;
    PORT
      LAYER Metal3 ;
        RECT 1878.010 239.680 1878.570 240.240 ;
    END
  END dmem_addr[5]
  PIN dmem_addr[6]
    DIRECTION OUTPUT ;
    USE SIGNAL ;
    ANTENNADIFFAREA 0.897600 ;
    PORT
      LAYER Metal3 ;
        RECT 1878.010 257.600 1878.570 258.160 ;
    END
  END dmem_addr[6]
  PIN dmem_addr[7]
    DIRECTION OUTPUT ;
    USE SIGNAL ;
    ANTENNADIFFAREA 0.897600 ;
    PORT
      LAYER Metal3 ;
        RECT 1878.010 275.520 1878.570 276.080 ;
    END
  END dmem_addr[7]
  PIN dmem_addr[8]
    DIRECTION OUTPUT ;
    USE SIGNAL ;
    ANTENNADIFFAREA 0.897600 ;
    PORT
      LAYER Metal3 ;
        RECT 1878.010 293.440 1878.570 294.000 ;
    END
  END dmem_addr[8]
  PIN dmem_addr[9]
    DIRECTION OUTPUT ;
    USE SIGNAL ;
    ANTENNADIFFAREA 0.897600 ;
    PORT
      LAYER Metal3 ;
        RECT 1878.010 311.360 1878.570 311.920 ;
    END
  END dmem_addr[9]
  PIN dmem_byte_enable[0]
    DIRECTION OUTPUT ;
    USE SIGNAL ;
    ANTENNADIFFAREA 0.897600 ;
    PORT
      LAYER Metal3 ;
        RECT 1878.010 78.400 1878.570 78.960 ;
    END
  END dmem_byte_enable[0]
  PIN dmem_byte_enable[1]
    DIRECTION OUTPUT ;
    USE SIGNAL ;
    ANTENNADIFFAREA 0.897600 ;
    PORT
      LAYER Metal3 ;
        RECT 1878.010 96.320 1878.570 96.880 ;
    END
  END dmem_byte_enable[1]
  PIN dmem_byte_enable[2]
    DIRECTION OUTPUT ;
    USE SIGNAL ;
    ANTENNADIFFAREA 0.897600 ;
    PORT
      LAYER Metal3 ;
        RECT 1878.010 114.240 1878.570 114.800 ;
    END
  END dmem_byte_enable[2]
  PIN dmem_byte_enable[3]
    DIRECTION OUTPUT ;
    USE SIGNAL ;
    ANTENNADIFFAREA 0.897600 ;
    PORT
      LAYER Metal3 ;
        RECT 1878.010 132.160 1878.570 132.720 ;
    END
  END dmem_byte_enable[3]
  PIN dmem_rdata[0]
    DIRECTION INPUT ;
    USE SIGNAL ;
    ANTENNAGATEAREA 0.741000 ;
    PORT
      LAYER Metal3 ;
        RECT 1878.010 1296.960 1878.570 1297.520 ;
    END
  END dmem_rdata[0]
  PIN dmem_rdata[10]
    DIRECTION INPUT ;
    USE SIGNAL ;
    ANTENNAGATEAREA 0.741000 ;
    PORT
      LAYER Metal3 ;
        RECT 1878.010 1476.160 1878.570 1476.720 ;
    END
  END dmem_rdata[10]
  PIN dmem_rdata[11]
    DIRECTION INPUT ;
    USE SIGNAL ;
    ANTENNAGATEAREA 0.741000 ;
    PORT
      LAYER Metal3 ;
        RECT 1878.010 1494.080 1878.570 1494.640 ;
    END
  END dmem_rdata[11]
  PIN dmem_rdata[12]
    DIRECTION INPUT ;
    USE SIGNAL ;
    ANTENNAGATEAREA 0.741000 ;
    PORT
      LAYER Metal3 ;
        RECT 1878.010 1512.000 1878.570 1512.560 ;
    END
  END dmem_rdata[12]
  PIN dmem_rdata[13]
    DIRECTION INPUT ;
    USE SIGNAL ;
    ANTENNAGATEAREA 0.741000 ;
    PORT
      LAYER Metal3 ;
        RECT 1878.010 1529.920 1878.570 1530.480 ;
    END
  END dmem_rdata[13]
  PIN dmem_rdata[14]
    DIRECTION INPUT ;
    USE SIGNAL ;
    ANTENNAGATEAREA 0.741000 ;
    PORT
      LAYER Metal3 ;
        RECT 1878.010 1547.840 1878.570 1548.400 ;
    END
  END dmem_rdata[14]
  PIN dmem_rdata[15]
    DIRECTION INPUT ;
    USE SIGNAL ;
    ANTENNAGATEAREA 0.741000 ;
    PORT
      LAYER Metal3 ;
        RECT 1878.010 1565.760 1878.570 1566.320 ;
    END
  END dmem_rdata[15]
  PIN dmem_rdata[16]
    DIRECTION INPUT ;
    USE SIGNAL ;
    ANTENNAGATEAREA 0.741000 ;
    PORT
      LAYER Metal3 ;
        RECT 1878.010 1583.680 1878.570 1584.240 ;
    END
  END dmem_rdata[16]
  PIN dmem_rdata[17]
    DIRECTION INPUT ;
    USE SIGNAL ;
    ANTENNAGATEAREA 0.741000 ;
    PORT
      LAYER Metal3 ;
        RECT 1878.010 1601.600 1878.570 1602.160 ;
    END
  END dmem_rdata[17]
  PIN dmem_rdata[18]
    DIRECTION INPUT ;
    USE SIGNAL ;
    ANTENNAGATEAREA 0.741000 ;
    PORT
      LAYER Metal3 ;
        RECT 1878.010 1619.520 1878.570 1620.080 ;
    END
  END dmem_rdata[18]
  PIN dmem_rdata[19]
    DIRECTION INPUT ;
    USE SIGNAL ;
    ANTENNAGATEAREA 0.741000 ;
    PORT
      LAYER Metal3 ;
        RECT 1878.010 1637.440 1878.570 1638.000 ;
    END
  END dmem_rdata[19]
  PIN dmem_rdata[1]
    DIRECTION INPUT ;
    USE SIGNAL ;
    ANTENNAGATEAREA 0.741000 ;
    PORT
      LAYER Metal3 ;
        RECT 1878.010 1314.880 1878.570 1315.440 ;
    END
  END dmem_rdata[1]
  PIN dmem_rdata[20]
    DIRECTION INPUT ;
    USE SIGNAL ;
    ANTENNAGATEAREA 0.741000 ;
    PORT
      LAYER Metal3 ;
        RECT 1878.010 1655.360 1878.570 1655.920 ;
    END
  END dmem_rdata[20]
  PIN dmem_rdata[21]
    DIRECTION INPUT ;
    USE SIGNAL ;
    ANTENNAGATEAREA 0.741000 ;
    PORT
      LAYER Metal3 ;
        RECT 1878.010 1673.280 1878.570 1673.840 ;
    END
  END dmem_rdata[21]
  PIN dmem_rdata[22]
    DIRECTION INPUT ;
    USE SIGNAL ;
    ANTENNAGATEAREA 0.741000 ;
    PORT
      LAYER Metal3 ;
        RECT 1878.010 1691.200 1878.570 1691.760 ;
    END
  END dmem_rdata[22]
  PIN dmem_rdata[23]
    DIRECTION INPUT ;
    USE SIGNAL ;
    ANTENNAGATEAREA 0.741000 ;
    PORT
      LAYER Metal3 ;
        RECT 1878.010 1709.120 1878.570 1709.680 ;
    END
  END dmem_rdata[23]
  PIN dmem_rdata[24]
    DIRECTION INPUT ;
    USE SIGNAL ;
    ANTENNAGATEAREA 0.741000 ;
    PORT
      LAYER Metal3 ;
        RECT 1878.010 1727.040 1878.570 1727.600 ;
    END
  END dmem_rdata[24]
  PIN dmem_rdata[25]
    DIRECTION INPUT ;
    USE SIGNAL ;
    ANTENNAGATEAREA 0.741000 ;
    PORT
      LAYER Metal3 ;
        RECT 1878.010 1744.960 1878.570 1745.520 ;
    END
  END dmem_rdata[25]
  PIN dmem_rdata[26]
    DIRECTION INPUT ;
    USE SIGNAL ;
    ANTENNAGATEAREA 0.741000 ;
    PORT
      LAYER Metal3 ;
        RECT 1878.010 1762.880 1878.570 1763.440 ;
    END
  END dmem_rdata[26]
  PIN dmem_rdata[27]
    DIRECTION INPUT ;
    USE SIGNAL ;
    ANTENNAGATEAREA 0.741000 ;
    PORT
      LAYER Metal3 ;
        RECT 1878.010 1780.800 1878.570 1781.360 ;
    END
  END dmem_rdata[27]
  PIN dmem_rdata[28]
    DIRECTION INPUT ;
    USE SIGNAL ;
    ANTENNAGATEAREA 0.741000 ;
    PORT
      LAYER Metal3 ;
        RECT 1878.010 1798.720 1878.570 1799.280 ;
    END
  END dmem_rdata[28]
  PIN dmem_rdata[29]
    DIRECTION INPUT ;
    USE SIGNAL ;
    ANTENNAGATEAREA 0.741000 ;
    PORT
      LAYER Metal3 ;
        RECT 1878.010 1816.640 1878.570 1817.200 ;
    END
  END dmem_rdata[29]
  PIN dmem_rdata[2]
    DIRECTION INPUT ;
    USE SIGNAL ;
    ANTENNAGATEAREA 0.741000 ;
    PORT
      LAYER Metal3 ;
        RECT 1878.010 1332.800 1878.570 1333.360 ;
    END
  END dmem_rdata[2]
  PIN dmem_rdata[30]
    DIRECTION INPUT ;
    USE SIGNAL ;
    ANTENNAGATEAREA 0.741000 ;
    PORT
      LAYER Metal3 ;
        RECT 1878.010 1834.560 1878.570 1835.120 ;
    END
  END dmem_rdata[30]
  PIN dmem_rdata[31]
    DIRECTION INPUT ;
    USE SIGNAL ;
    ANTENNAGATEAREA 0.741000 ;
    PORT
      LAYER Metal3 ;
        RECT 1878.010 1852.480 1878.570 1853.040 ;
    END
  END dmem_rdata[31]
  PIN dmem_rdata[3]
    DIRECTION INPUT ;
    USE SIGNAL ;
    ANTENNAGATEAREA 0.741000 ;
    PORT
      LAYER Metal3 ;
        RECT 1878.010 1350.720 1878.570 1351.280 ;
    END
  END dmem_rdata[3]
  PIN dmem_rdata[4]
    DIRECTION INPUT ;
    USE SIGNAL ;
    ANTENNAGATEAREA 0.741000 ;
    PORT
      LAYER Metal3 ;
        RECT 1878.010 1368.640 1878.570 1369.200 ;
    END
  END dmem_rdata[4]
  PIN dmem_rdata[5]
    DIRECTION INPUT ;
    USE SIGNAL ;
    ANTENNAGATEAREA 0.741000 ;
    PORT
      LAYER Metal3 ;
        RECT 1878.010 1386.560 1878.570 1387.120 ;
    END
  END dmem_rdata[5]
  PIN dmem_rdata[6]
    DIRECTION INPUT ;
    USE SIGNAL ;
    ANTENNAGATEAREA 0.741000 ;
    PORT
      LAYER Metal3 ;
        RECT 1878.010 1404.480 1878.570 1405.040 ;
    END
  END dmem_rdata[6]
  PIN dmem_rdata[7]
    DIRECTION INPUT ;
    USE SIGNAL ;
    ANTENNAGATEAREA 0.741000 ;
    PORT
      LAYER Metal3 ;
        RECT 1878.010 1422.400 1878.570 1422.960 ;
    END
  END dmem_rdata[7]
  PIN dmem_rdata[8]
    DIRECTION INPUT ;
    USE SIGNAL ;
    ANTENNAGATEAREA 0.741000 ;
    PORT
      LAYER Metal3 ;
        RECT 1878.010 1440.320 1878.570 1440.880 ;
    END
  END dmem_rdata[8]
  PIN dmem_rdata[9]
    DIRECTION INPUT ;
    USE SIGNAL ;
    ANTENNAGATEAREA 0.741000 ;
    PORT
      LAYER Metal3 ;
        RECT 1878.010 1458.240 1878.570 1458.800 ;
    END
  END dmem_rdata[9]
  PIN dmem_req
    DIRECTION OUTPUT ;
    USE SIGNAL ;
    ANTENNADIFFAREA 0.897600 ;
    PORT
      LAYER Metal3 ;
        RECT 1878.010 42.560 1878.570 43.120 ;
    END
  END dmem_req
  PIN dmem_wdata[0]
    DIRECTION OUTPUT ;
    USE SIGNAL ;
    ANTENNADIFFAREA 0.897600 ;
    PORT
      LAYER Metal3 ;
        RECT 1878.010 723.520 1878.570 724.080 ;
    END
  END dmem_wdata[0]
  PIN dmem_wdata[10]
    DIRECTION OUTPUT ;
    USE SIGNAL ;
    ANTENNADIFFAREA 0.897600 ;
    PORT
      LAYER Metal3 ;
        RECT 1878.010 902.720 1878.570 903.280 ;
    END
  END dmem_wdata[10]
  PIN dmem_wdata[11]
    DIRECTION OUTPUT ;
    USE SIGNAL ;
    ANTENNADIFFAREA 0.897600 ;
    PORT
      LAYER Metal3 ;
        RECT 1878.010 920.640 1878.570 921.200 ;
    END
  END dmem_wdata[11]
  PIN dmem_wdata[12]
    DIRECTION OUTPUT ;
    USE SIGNAL ;
    ANTENNADIFFAREA 0.897600 ;
    PORT
      LAYER Metal3 ;
        RECT 1878.010 938.560 1878.570 939.120 ;
    END
  END dmem_wdata[12]
  PIN dmem_wdata[13]
    DIRECTION OUTPUT ;
    USE SIGNAL ;
    ANTENNADIFFAREA 0.897600 ;
    PORT
      LAYER Metal3 ;
        RECT 1878.010 956.480 1878.570 957.040 ;
    END
  END dmem_wdata[13]
  PIN dmem_wdata[14]
    DIRECTION OUTPUT ;
    USE SIGNAL ;
    ANTENNADIFFAREA 0.897600 ;
    PORT
      LAYER Metal3 ;
        RECT 1878.010 974.400 1878.570 974.960 ;
    END
  END dmem_wdata[14]
  PIN dmem_wdata[15]
    DIRECTION OUTPUT ;
    USE SIGNAL ;
    ANTENNADIFFAREA 0.897600 ;
    PORT
      LAYER Metal3 ;
        RECT 1878.010 992.320 1878.570 992.880 ;
    END
  END dmem_wdata[15]
  PIN dmem_wdata[16]
    DIRECTION OUTPUT ;
    USE SIGNAL ;
    ANTENNADIFFAREA 0.897600 ;
    PORT
      LAYER Metal3 ;
        RECT 1878.010 1010.240 1878.570 1010.800 ;
    END
  END dmem_wdata[16]
  PIN dmem_wdata[17]
    DIRECTION OUTPUT ;
    USE SIGNAL ;
    ANTENNADIFFAREA 0.897600 ;
    PORT
      LAYER Metal3 ;
        RECT 1878.010 1028.160 1878.570 1028.720 ;
    END
  END dmem_wdata[17]
  PIN dmem_wdata[18]
    DIRECTION OUTPUT ;
    USE SIGNAL ;
    ANTENNADIFFAREA 0.897600 ;
    PORT
      LAYER Metal3 ;
        RECT 1878.010 1046.080 1878.570 1046.640 ;
    END
  END dmem_wdata[18]
  PIN dmem_wdata[19]
    DIRECTION OUTPUT ;
    USE SIGNAL ;
    ANTENNADIFFAREA 0.897600 ;
    PORT
      LAYER Metal3 ;
        RECT 1878.010 1064.000 1878.570 1064.560 ;
    END
  END dmem_wdata[19]
  PIN dmem_wdata[1]
    DIRECTION OUTPUT ;
    USE SIGNAL ;
    ANTENNADIFFAREA 0.897600 ;
    PORT
      LAYER Metal3 ;
        RECT 1878.010 741.440 1878.570 742.000 ;
    END
  END dmem_wdata[1]
  PIN dmem_wdata[20]
    DIRECTION OUTPUT ;
    USE SIGNAL ;
    ANTENNADIFFAREA 0.897600 ;
    PORT
      LAYER Metal3 ;
        RECT 1878.010 1081.920 1878.570 1082.480 ;
    END
  END dmem_wdata[20]
  PIN dmem_wdata[21]
    DIRECTION OUTPUT ;
    USE SIGNAL ;
    ANTENNADIFFAREA 0.897600 ;
    PORT
      LAYER Metal3 ;
        RECT 1878.010 1099.840 1878.570 1100.400 ;
    END
  END dmem_wdata[21]
  PIN dmem_wdata[22]
    DIRECTION OUTPUT ;
    USE SIGNAL ;
    ANTENNADIFFAREA 0.897600 ;
    PORT
      LAYER Metal3 ;
        RECT 1878.010 1117.760 1878.570 1118.320 ;
    END
  END dmem_wdata[22]
  PIN dmem_wdata[23]
    DIRECTION OUTPUT ;
    USE SIGNAL ;
    ANTENNADIFFAREA 0.897600 ;
    PORT
      LAYER Metal3 ;
        RECT 1878.010 1135.680 1878.570 1136.240 ;
    END
  END dmem_wdata[23]
  PIN dmem_wdata[24]
    DIRECTION OUTPUT ;
    USE SIGNAL ;
    ANTENNADIFFAREA 0.897600 ;
    PORT
      LAYER Metal3 ;
        RECT 1878.010 1153.600 1878.570 1154.160 ;
    END
  END dmem_wdata[24]
  PIN dmem_wdata[25]
    DIRECTION OUTPUT ;
    USE SIGNAL ;
    ANTENNADIFFAREA 0.897600 ;
    PORT
      LAYER Metal3 ;
        RECT 1878.010 1171.520 1878.570 1172.080 ;
    END
  END dmem_wdata[25]
  PIN dmem_wdata[26]
    DIRECTION OUTPUT ;
    USE SIGNAL ;
    ANTENNADIFFAREA 0.897600 ;
    PORT
      LAYER Metal3 ;
        RECT 1878.010 1189.440 1878.570 1190.000 ;
    END
  END dmem_wdata[26]
  PIN dmem_wdata[27]
    DIRECTION OUTPUT ;
    USE SIGNAL ;
    ANTENNADIFFAREA 0.897600 ;
    PORT
      LAYER Metal3 ;
        RECT 1878.010 1207.360 1878.570 1207.920 ;
    END
  END dmem_wdata[27]
  PIN dmem_wdata[28]
    DIRECTION OUTPUT ;
    USE SIGNAL ;
    ANTENNADIFFAREA 0.897600 ;
    PORT
      LAYER Metal3 ;
        RECT 1878.010 1225.280 1878.570 1225.840 ;
    END
  END dmem_wdata[28]
  PIN dmem_wdata[29]
    DIRECTION OUTPUT ;
    USE SIGNAL ;
    ANTENNADIFFAREA 0.897600 ;
    PORT
      LAYER Metal3 ;
        RECT 1878.010 1243.200 1878.570 1243.760 ;
    END
  END dmem_wdata[29]
  PIN dmem_wdata[2]
    DIRECTION OUTPUT ;
    USE SIGNAL ;
    ANTENNADIFFAREA 0.897600 ;
    PORT
      LAYER Metal3 ;
        RECT 1878.010 759.360 1878.570 759.920 ;
    END
  END dmem_wdata[2]
  PIN dmem_wdata[30]
    DIRECTION OUTPUT ;
    USE SIGNAL ;
    ANTENNADIFFAREA 0.897600 ;
    PORT
      LAYER Metal3 ;
        RECT 1878.010 1261.120 1878.570 1261.680 ;
    END
  END dmem_wdata[30]
  PIN dmem_wdata[31]
    DIRECTION OUTPUT ;
    USE SIGNAL ;
    ANTENNADIFFAREA 0.897600 ;
    PORT
      LAYER Metal3 ;
        RECT 1878.010 1279.040 1878.570 1279.600 ;
    END
  END dmem_wdata[31]
  PIN dmem_wdata[3]
    DIRECTION OUTPUT ;
    USE SIGNAL ;
    ANTENNADIFFAREA 0.897600 ;
    PORT
      LAYER Metal3 ;
        RECT 1878.010 777.280 1878.570 777.840 ;
    END
  END dmem_wdata[3]
  PIN dmem_wdata[4]
    DIRECTION OUTPUT ;
    USE SIGNAL ;
    ANTENNADIFFAREA 0.897600 ;
    PORT
      LAYER Metal3 ;
        RECT 1878.010 795.200 1878.570 795.760 ;
    END
  END dmem_wdata[4]
  PIN dmem_wdata[5]
    DIRECTION OUTPUT ;
    USE SIGNAL ;
    ANTENNADIFFAREA 0.897600 ;
    PORT
      LAYER Metal3 ;
        RECT 1878.010 813.120 1878.570 813.680 ;
    END
  END dmem_wdata[5]
  PIN dmem_wdata[6]
    DIRECTION OUTPUT ;
    USE SIGNAL ;
    ANTENNADIFFAREA 0.897600 ;
    PORT
      LAYER Metal3 ;
        RECT 1878.010 831.040 1878.570 831.600 ;
    END
  END dmem_wdata[6]
  PIN dmem_wdata[7]
    DIRECTION OUTPUT ;
    USE SIGNAL ;
    ANTENNADIFFAREA 0.897600 ;
    PORT
      LAYER Metal3 ;
        RECT 1878.010 848.960 1878.570 849.520 ;
    END
  END dmem_wdata[7]
  PIN dmem_wdata[8]
    DIRECTION OUTPUT ;
    USE SIGNAL ;
    ANTENNADIFFAREA 0.897600 ;
    PORT
      LAYER Metal3 ;
        RECT 1878.010 866.880 1878.570 867.440 ;
    END
  END dmem_wdata[8]
  PIN dmem_wdata[9]
    DIRECTION OUTPUT ;
    USE SIGNAL ;
    ANTENNADIFFAREA 0.897600 ;
    PORT
      LAYER Metal3 ;
        RECT 1878.010 884.800 1878.570 885.360 ;
    END
  END dmem_wdata[9]
  PIN dmem_we
    DIRECTION OUTPUT ;
    USE SIGNAL ;
    ANTENNADIFFAREA 0.897600 ;
    PORT
      LAYER Metal3 ;
        RECT 1878.010 60.480 1878.570 61.040 ;
    END
  END dmem_we
  PIN imem_addr[0]
    DIRECTION OUTPUT ;
    USE SIGNAL ;
    ANTENNADIFFAREA 0.897600 ;
    PORT
      LAYER Metal2 ;
        RECT 21.280 1895.930 21.840 1896.490 ;
    END
  END imem_addr[0]
  PIN imem_addr[10]
    DIRECTION OUTPUT ;
    USE SIGNAL ;
    ANTENNADIFFAREA 0.897600 ;
    PORT
      LAYER Metal2 ;
        RECT 312.480 1895.930 313.040 1896.490 ;
    END
  END imem_addr[10]
  PIN imem_addr[11]
    DIRECTION OUTPUT ;
    USE SIGNAL ;
    ANTENNADIFFAREA 0.897600 ;
    PORT
      LAYER Metal2 ;
        RECT 341.600 1895.930 342.160 1896.490 ;
    END
  END imem_addr[11]
  PIN imem_addr[12]
    DIRECTION OUTPUT ;
    USE SIGNAL ;
    ANTENNADIFFAREA 0.897600 ;
    PORT
      LAYER Metal2 ;
        RECT 370.720 1895.930 371.280 1896.490 ;
    END
  END imem_addr[12]
  PIN imem_addr[13]
    DIRECTION OUTPUT ;
    USE SIGNAL ;
    ANTENNADIFFAREA 0.897600 ;
    PORT
      LAYER Metal2 ;
        RECT 399.840 1895.930 400.400 1896.490 ;
    END
  END imem_addr[13]
  PIN imem_addr[14]
    DIRECTION OUTPUT ;
    USE SIGNAL ;
    ANTENNADIFFAREA 0.897600 ;
    PORT
      LAYER Metal2 ;
        RECT 428.960 1895.930 429.520 1896.490 ;
    END
  END imem_addr[14]
  PIN imem_addr[15]
    DIRECTION OUTPUT ;
    USE SIGNAL ;
    ANTENNADIFFAREA 0.897600 ;
    PORT
      LAYER Metal2 ;
        RECT 458.080 1895.930 458.640 1896.490 ;
    END
  END imem_addr[15]
  PIN imem_addr[16]
    DIRECTION OUTPUT ;
    USE SIGNAL ;
    ANTENNADIFFAREA 0.897600 ;
    PORT
      LAYER Metal2 ;
        RECT 487.200 1895.930 487.760 1896.490 ;
    END
  END imem_addr[16]
  PIN imem_addr[17]
    DIRECTION OUTPUT ;
    USE SIGNAL ;
    ANTENNADIFFAREA 0.897600 ;
    PORT
      LAYER Metal2 ;
        RECT 516.320 1895.930 516.880 1896.490 ;
    END
  END imem_addr[17]
  PIN imem_addr[18]
    DIRECTION OUTPUT ;
    USE SIGNAL ;
    ANTENNADIFFAREA 0.897600 ;
    PORT
      LAYER Metal2 ;
        RECT 545.440 1895.930 546.000 1896.490 ;
    END
  END imem_addr[18]
  PIN imem_addr[19]
    DIRECTION OUTPUT ;
    USE SIGNAL ;
    ANTENNADIFFAREA 0.897600 ;
    PORT
      LAYER Metal2 ;
        RECT 574.560 1895.930 575.120 1896.490 ;
    END
  END imem_addr[19]
  PIN imem_addr[1]
    DIRECTION OUTPUT ;
    USE SIGNAL ;
    ANTENNADIFFAREA 0.897600 ;
    PORT
      LAYER Metal2 ;
        RECT 50.400 1895.930 50.960 1896.490 ;
    END
  END imem_addr[1]
  PIN imem_addr[20]
    DIRECTION OUTPUT ;
    USE SIGNAL ;
    ANTENNADIFFAREA 0.897600 ;
    PORT
      LAYER Metal2 ;
        RECT 603.680 1895.930 604.240 1896.490 ;
    END
  END imem_addr[20]
  PIN imem_addr[21]
    DIRECTION OUTPUT ;
    USE SIGNAL ;
    ANTENNADIFFAREA 0.897600 ;
    PORT
      LAYER Metal2 ;
        RECT 632.800 1895.930 633.360 1896.490 ;
    END
  END imem_addr[21]
  PIN imem_addr[22]
    DIRECTION OUTPUT ;
    USE SIGNAL ;
    ANTENNADIFFAREA 0.897600 ;
    PORT
      LAYER Metal2 ;
        RECT 661.920 1895.930 662.480 1896.490 ;
    END
  END imem_addr[22]
  PIN imem_addr[23]
    DIRECTION OUTPUT ;
    USE SIGNAL ;
    ANTENNADIFFAREA 0.897600 ;
    PORT
      LAYER Metal2 ;
        RECT 691.040 1895.930 691.600 1896.490 ;
    END
  END imem_addr[23]
  PIN imem_addr[24]
    DIRECTION OUTPUT ;
    USE SIGNAL ;
    ANTENNADIFFAREA 0.897600 ;
    PORT
      LAYER Metal2 ;
        RECT 720.160 1895.930 720.720 1896.490 ;
    END
  END imem_addr[24]
  PIN imem_addr[25]
    DIRECTION OUTPUT ;
    USE SIGNAL ;
    ANTENNADIFFAREA 0.897600 ;
    PORT
      LAYER Metal2 ;
        RECT 749.280 1895.930 749.840 1896.490 ;
    END
  END imem_addr[25]
  PIN imem_addr[26]
    DIRECTION OUTPUT ;
    USE SIGNAL ;
    ANTENNADIFFAREA 0.897600 ;
    PORT
      LAYER Metal2 ;
        RECT 778.400 1895.930 778.960 1896.490 ;
    END
  END imem_addr[26]
  PIN imem_addr[27]
    DIRECTION OUTPUT ;
    USE SIGNAL ;
    ANTENNADIFFAREA 0.897600 ;
    PORT
      LAYER Metal2 ;
        RECT 807.520 1895.930 808.080 1896.490 ;
    END
  END imem_addr[27]
  PIN imem_addr[28]
    DIRECTION OUTPUT ;
    USE SIGNAL ;
    ANTENNADIFFAREA 0.897600 ;
    PORT
      LAYER Metal2 ;
        RECT 836.640 1895.930 837.200 1896.490 ;
    END
  END imem_addr[28]
  PIN imem_addr[29]
    DIRECTION OUTPUT ;
    USE SIGNAL ;
    ANTENNADIFFAREA 0.897600 ;
    PORT
      LAYER Metal2 ;
        RECT 865.760 1895.930 866.320 1896.490 ;
    END
  END imem_addr[29]
  PIN imem_addr[2]
    DIRECTION OUTPUT ;
    USE SIGNAL ;
    ANTENNADIFFAREA 0.897600 ;
    PORT
      LAYER Metal2 ;
        RECT 79.520 1895.930 80.080 1896.490 ;
    END
  END imem_addr[2]
  PIN imem_addr[30]
    DIRECTION OUTPUT ;
    USE SIGNAL ;
    ANTENNADIFFAREA 0.897600 ;
    PORT
      LAYER Metal2 ;
        RECT 894.880 1895.930 895.440 1896.490 ;
    END
  END imem_addr[30]
  PIN imem_addr[31]
    DIRECTION OUTPUT ;
    USE SIGNAL ;
    ANTENNADIFFAREA 0.897600 ;
    PORT
      LAYER Metal2 ;
        RECT 924.000 1895.930 924.560 1896.490 ;
    END
  END imem_addr[31]
  PIN imem_addr[3]
    DIRECTION OUTPUT ;
    USE SIGNAL ;
    ANTENNADIFFAREA 0.897600 ;
    PORT
      LAYER Metal2 ;
        RECT 108.640 1895.930 109.200 1896.490 ;
    END
  END imem_addr[3]
  PIN imem_addr[4]
    DIRECTION OUTPUT ;
    USE SIGNAL ;
    ANTENNADIFFAREA 0.897600 ;
    PORT
      LAYER Metal2 ;
        RECT 137.760 1895.930 138.320 1896.490 ;
    END
  END imem_addr[4]
  PIN imem_addr[5]
    DIRECTION OUTPUT ;
    USE SIGNAL ;
    ANTENNADIFFAREA 0.897600 ;
    PORT
      LAYER Metal2 ;
        RECT 166.880 1895.930 167.440 1896.490 ;
    END
  END imem_addr[5]
  PIN imem_addr[6]
    DIRECTION OUTPUT ;
    USE SIGNAL ;
    ANTENNADIFFAREA 0.897600 ;
    PORT
      LAYER Metal2 ;
        RECT 196.000 1895.930 196.560 1896.490 ;
    END
  END imem_addr[6]
  PIN imem_addr[7]
    DIRECTION OUTPUT ;
    USE SIGNAL ;
    ANTENNADIFFAREA 0.897600 ;
    PORT
      LAYER Metal2 ;
        RECT 225.120 1895.930 225.680 1896.490 ;
    END
  END imem_addr[7]
  PIN imem_addr[8]
    DIRECTION OUTPUT ;
    USE SIGNAL ;
    ANTENNADIFFAREA 0.897600 ;
    PORT
      LAYER Metal2 ;
        RECT 254.240 1895.930 254.800 1896.490 ;
    END
  END imem_addr[8]
  PIN imem_addr[9]
    DIRECTION OUTPUT ;
    USE SIGNAL ;
    ANTENNADIFFAREA 0.897600 ;
    PORT
      LAYER Metal2 ;
        RECT 283.360 1895.930 283.920 1896.490 ;
    END
  END imem_addr[9]
  PIN imem_rdata[0]
    DIRECTION INPUT ;
    USE SIGNAL ;
    ANTENNAGATEAREA 0.741000 ;
    PORT
      LAYER Metal2 ;
        RECT 953.120 1895.930 953.680 1896.490 ;
    END
  END imem_rdata[0]
  PIN imem_rdata[10]
    DIRECTION INPUT ;
    USE SIGNAL ;
    ANTENNAGATEAREA 0.741000 ;
    PORT
      LAYER Metal2 ;
        RECT 1244.320 1895.930 1244.880 1896.490 ;
    END
  END imem_rdata[10]
  PIN imem_rdata[11]
    DIRECTION INPUT ;
    USE SIGNAL ;
    ANTENNAGATEAREA 0.741000 ;
    PORT
      LAYER Metal2 ;
        RECT 1273.440 1895.930 1274.000 1896.490 ;
    END
  END imem_rdata[11]
  PIN imem_rdata[12]
    DIRECTION INPUT ;
    USE SIGNAL ;
    ANTENNAGATEAREA 0.741000 ;
    PORT
      LAYER Metal2 ;
        RECT 1302.560 1895.930 1303.120 1896.490 ;
    END
  END imem_rdata[12]
  PIN imem_rdata[13]
    DIRECTION INPUT ;
    USE SIGNAL ;
    ANTENNAGATEAREA 0.741000 ;
    PORT
      LAYER Metal2 ;
        RECT 1331.680 1895.930 1332.240 1896.490 ;
    END
  END imem_rdata[13]
  PIN imem_rdata[14]
    DIRECTION INPUT ;
    USE SIGNAL ;
    ANTENNAGATEAREA 0.741000 ;
    PORT
      LAYER Metal2 ;
        RECT 1360.800 1895.930 1361.360 1896.490 ;
    END
  END imem_rdata[14]
  PIN imem_rdata[15]
    DIRECTION INPUT ;
    USE SIGNAL ;
    ANTENNAGATEAREA 0.741000 ;
    PORT
      LAYER Metal2 ;
        RECT 1389.920 1895.930 1390.480 1896.490 ;
    END
  END imem_rdata[15]
  PIN imem_rdata[16]
    DIRECTION INPUT ;
    USE SIGNAL ;
    ANTENNAGATEAREA 0.741000 ;
    PORT
      LAYER Metal2 ;
        RECT 1419.040 1895.930 1419.600 1896.490 ;
    END
  END imem_rdata[16]
  PIN imem_rdata[17]
    DIRECTION INPUT ;
    USE SIGNAL ;
    ANTENNAGATEAREA 0.741000 ;
    PORT
      LAYER Metal2 ;
        RECT 1448.160 1895.930 1448.720 1896.490 ;
    END
  END imem_rdata[17]
  PIN imem_rdata[18]
    DIRECTION INPUT ;
    USE SIGNAL ;
    ANTENNAGATEAREA 0.741000 ;
    PORT
      LAYER Metal2 ;
        RECT 1477.280 1895.930 1477.840 1896.490 ;
    END
  END imem_rdata[18]
  PIN imem_rdata[19]
    DIRECTION INPUT ;
    USE SIGNAL ;
    ANTENNAGATEAREA 0.741000 ;
    PORT
      LAYER Metal2 ;
        RECT 1506.400 1895.930 1506.960 1896.490 ;
    END
  END imem_rdata[19]
  PIN imem_rdata[1]
    DIRECTION INPUT ;
    USE SIGNAL ;
    ANTENNAGATEAREA 0.741000 ;
    PORT
      LAYER Metal2 ;
        RECT 982.240 1895.930 982.800 1896.490 ;
    END
  END imem_rdata[1]
  PIN imem_rdata[20]
    DIRECTION INPUT ;
    USE SIGNAL ;
    ANTENNAGATEAREA 0.741000 ;
    PORT
      LAYER Metal2 ;
        RECT 1535.520 1895.930 1536.080 1896.490 ;
    END
  END imem_rdata[20]
  PIN imem_rdata[21]
    DIRECTION INPUT ;
    USE SIGNAL ;
    ANTENNAGATEAREA 0.741000 ;
    PORT
      LAYER Metal2 ;
        RECT 1564.640 1895.930 1565.200 1896.490 ;
    END
  END imem_rdata[21]
  PIN imem_rdata[22]
    DIRECTION INPUT ;
    USE SIGNAL ;
    ANTENNAGATEAREA 0.741000 ;
    PORT
      LAYER Metal2 ;
        RECT 1593.760 1895.930 1594.320 1896.490 ;
    END
  END imem_rdata[22]
  PIN imem_rdata[23]
    DIRECTION INPUT ;
    USE SIGNAL ;
    ANTENNAGATEAREA 0.741000 ;
    PORT
      LAYER Metal2 ;
        RECT 1622.880 1895.930 1623.440 1896.490 ;
    END
  END imem_rdata[23]
  PIN imem_rdata[24]
    DIRECTION INPUT ;
    USE SIGNAL ;
    ANTENNAGATEAREA 0.741000 ;
    PORT
      LAYER Metal2 ;
        RECT 1652.000 1895.930 1652.560 1896.490 ;
    END
  END imem_rdata[24]
  PIN imem_rdata[25]
    DIRECTION INPUT ;
    USE SIGNAL ;
    ANTENNAGATEAREA 0.741000 ;
    PORT
      LAYER Metal2 ;
        RECT 1681.120 1895.930 1681.680 1896.490 ;
    END
  END imem_rdata[25]
  PIN imem_rdata[26]
    DIRECTION INPUT ;
    USE SIGNAL ;
    ANTENNAGATEAREA 0.741000 ;
    PORT
      LAYER Metal2 ;
        RECT 1710.240 1895.930 1710.800 1896.490 ;
    END
  END imem_rdata[26]
  PIN imem_rdata[27]
    DIRECTION INPUT ;
    USE SIGNAL ;
    ANTENNAGATEAREA 0.741000 ;
    PORT
      LAYER Metal2 ;
        RECT 1739.360 1895.930 1739.920 1896.490 ;
    END
  END imem_rdata[27]
  PIN imem_rdata[28]
    DIRECTION INPUT ;
    USE SIGNAL ;
    ANTENNAGATEAREA 0.741000 ;
    PORT
      LAYER Metal2 ;
        RECT 1768.480 1895.930 1769.040 1896.490 ;
    END
  END imem_rdata[28]
  PIN imem_rdata[29]
    DIRECTION INPUT ;
    USE SIGNAL ;
    ANTENNAGATEAREA 0.741000 ;
    PORT
      LAYER Metal2 ;
        RECT 1797.600 1895.930 1798.160 1896.490 ;
    END
  END imem_rdata[29]
  PIN imem_rdata[2]
    DIRECTION INPUT ;
    USE SIGNAL ;
    ANTENNAGATEAREA 0.741000 ;
    PORT
      LAYER Metal2 ;
        RECT 1011.360 1895.930 1011.920 1896.490 ;
    END
  END imem_rdata[2]
  PIN imem_rdata[30]
    DIRECTION INPUT ;
    USE SIGNAL ;
    ANTENNAGATEAREA 0.741000 ;
    PORT
      LAYER Metal2 ;
        RECT 1826.720 1895.930 1827.280 1896.490 ;
    END
  END imem_rdata[30]
  PIN imem_rdata[31]
    DIRECTION INPUT ;
    USE SIGNAL ;
    ANTENNAGATEAREA 0.741000 ;
    PORT
      LAYER Metal2 ;
        RECT 1855.840 1895.930 1856.400 1896.490 ;
    END
  END imem_rdata[31]
  PIN imem_rdata[3]
    DIRECTION INPUT ;
    USE SIGNAL ;
    ANTENNAGATEAREA 0.741000 ;
    PORT
      LAYER Metal2 ;
        RECT 1040.480 1895.930 1041.040 1896.490 ;
    END
  END imem_rdata[3]
  PIN imem_rdata[4]
    DIRECTION INPUT ;
    USE SIGNAL ;
    ANTENNAGATEAREA 0.741000 ;
    PORT
      LAYER Metal2 ;
        RECT 1069.600 1895.930 1070.160 1896.490 ;
    END
  END imem_rdata[4]
  PIN imem_rdata[5]
    DIRECTION INPUT ;
    USE SIGNAL ;
    ANTENNAGATEAREA 0.741000 ;
    PORT
      LAYER Metal2 ;
        RECT 1098.720 1895.930 1099.280 1896.490 ;
    END
  END imem_rdata[5]
  PIN imem_rdata[6]
    DIRECTION INPUT ;
    USE SIGNAL ;
    ANTENNAGATEAREA 0.741000 ;
    PORT
      LAYER Metal2 ;
        RECT 1127.840 1895.930 1128.400 1896.490 ;
    END
  END imem_rdata[6]
  PIN imem_rdata[7]
    DIRECTION INPUT ;
    USE SIGNAL ;
    ANTENNAGATEAREA 0.741000 ;
    PORT
      LAYER Metal2 ;
        RECT 1156.960 1895.930 1157.520 1896.490 ;
    END
  END imem_rdata[7]
  PIN imem_rdata[8]
    DIRECTION INPUT ;
    USE SIGNAL ;
    ANTENNAGATEAREA 0.741000 ;
    PORT
      LAYER Metal2 ;
        RECT 1186.080 1895.930 1186.640 1896.490 ;
    END
  END imem_rdata[8]
  PIN imem_rdata[9]
    DIRECTION INPUT ;
    USE SIGNAL ;
    ANTENNAGATEAREA 0.741000 ;
    PORT
      LAYER Metal2 ;
        RECT 1215.200 1895.930 1215.760 1896.490 ;
    END
  END imem_rdata[9]
  PIN rst_n
    DIRECTION INPUT ;
    USE SIGNAL ;
    ANTENNAGATEAREA 0.741000 ;
    PORT
      LAYER Metal2 ;
        RECT 563.360 0.000 563.920 0.560 ;
    END
  END rst_n
  OBS
      LAYER Nwell ;
        RECT 6.290 15.250 1871.950 1878.110 ;
      LAYER Metal1 ;
        RECT 6.720 15.380 1871.520 1877.980 ;
      LAYER Metal2 ;
        RECT 2.380 1895.630 20.980 1896.350 ;
        RECT 22.140 1895.630 50.100 1896.350 ;
        RECT 51.260 1895.630 79.220 1896.350 ;
        RECT 80.380 1895.630 108.340 1896.350 ;
        RECT 109.500 1895.630 137.460 1896.350 ;
        RECT 138.620 1895.630 166.580 1896.350 ;
        RECT 167.740 1895.630 195.700 1896.350 ;
        RECT 196.860 1895.630 224.820 1896.350 ;
        RECT 225.980 1895.630 253.940 1896.350 ;
        RECT 255.100 1895.630 283.060 1896.350 ;
        RECT 284.220 1895.630 312.180 1896.350 ;
        RECT 313.340 1895.630 341.300 1896.350 ;
        RECT 342.460 1895.630 370.420 1896.350 ;
        RECT 371.580 1895.630 399.540 1896.350 ;
        RECT 400.700 1895.630 428.660 1896.350 ;
        RECT 429.820 1895.630 457.780 1896.350 ;
        RECT 458.940 1895.630 486.900 1896.350 ;
        RECT 488.060 1895.630 516.020 1896.350 ;
        RECT 517.180 1895.630 545.140 1896.350 ;
        RECT 546.300 1895.630 574.260 1896.350 ;
        RECT 575.420 1895.630 603.380 1896.350 ;
        RECT 604.540 1895.630 632.500 1896.350 ;
        RECT 633.660 1895.630 661.620 1896.350 ;
        RECT 662.780 1895.630 690.740 1896.350 ;
        RECT 691.900 1895.630 719.860 1896.350 ;
        RECT 721.020 1895.630 748.980 1896.350 ;
        RECT 750.140 1895.630 778.100 1896.350 ;
        RECT 779.260 1895.630 807.220 1896.350 ;
        RECT 808.380 1895.630 836.340 1896.350 ;
        RECT 837.500 1895.630 865.460 1896.350 ;
        RECT 866.620 1895.630 894.580 1896.350 ;
        RECT 895.740 1895.630 923.700 1896.350 ;
        RECT 924.860 1895.630 952.820 1896.350 ;
        RECT 953.980 1895.630 981.940 1896.350 ;
        RECT 983.100 1895.630 1011.060 1896.350 ;
        RECT 1012.220 1895.630 1040.180 1896.350 ;
        RECT 1041.340 1895.630 1069.300 1896.350 ;
        RECT 1070.460 1895.630 1098.420 1896.350 ;
        RECT 1099.580 1895.630 1127.540 1896.350 ;
        RECT 1128.700 1895.630 1156.660 1896.350 ;
        RECT 1157.820 1895.630 1185.780 1896.350 ;
        RECT 1186.940 1895.630 1214.900 1896.350 ;
        RECT 1216.060 1895.630 1244.020 1896.350 ;
        RECT 1245.180 1895.630 1273.140 1896.350 ;
        RECT 1274.300 1895.630 1302.260 1896.350 ;
        RECT 1303.420 1895.630 1331.380 1896.350 ;
        RECT 1332.540 1895.630 1360.500 1896.350 ;
        RECT 1361.660 1895.630 1389.620 1896.350 ;
        RECT 1390.780 1895.630 1418.740 1896.350 ;
        RECT 1419.900 1895.630 1447.860 1896.350 ;
        RECT 1449.020 1895.630 1476.980 1896.350 ;
        RECT 1478.140 1895.630 1506.100 1896.350 ;
        RECT 1507.260 1895.630 1535.220 1896.350 ;
        RECT 1536.380 1895.630 1564.340 1896.350 ;
        RECT 1565.500 1895.630 1593.460 1896.350 ;
        RECT 1594.620 1895.630 1622.580 1896.350 ;
        RECT 1623.740 1895.630 1651.700 1896.350 ;
        RECT 1652.860 1895.630 1680.820 1896.350 ;
        RECT 1681.980 1895.630 1709.940 1896.350 ;
        RECT 1711.100 1895.630 1739.060 1896.350 ;
        RECT 1740.220 1895.630 1768.180 1896.350 ;
        RECT 1769.340 1895.630 1797.300 1896.350 ;
        RECT 1798.460 1895.630 1826.420 1896.350 ;
        RECT 1827.580 1895.630 1855.540 1896.350 ;
        RECT 1856.700 1895.630 1878.100 1896.350 ;
        RECT 2.380 0.860 1878.100 1895.630 ;
        RECT 2.380 0.090 187.860 0.860 ;
        RECT 189.020 0.090 563.060 0.860 ;
        RECT 564.220 0.090 938.260 0.860 ;
        RECT 939.420 0.090 1313.460 0.860 ;
        RECT 1314.620 0.090 1688.660 0.860 ;
        RECT 1689.820 0.090 1878.100 0.860 ;
      LAYER Metal3 ;
        RECT 0.560 1853.340 1878.430 1894.340 ;
        RECT 0.560 1852.180 1877.710 1853.340 ;
        RECT 0.560 1848.860 1878.430 1852.180 ;
        RECT 0.860 1847.700 1878.430 1848.860 ;
        RECT 0.560 1835.420 1878.430 1847.700 ;
        RECT 0.860 1834.260 1877.710 1835.420 ;
        RECT 0.560 1821.980 1878.430 1834.260 ;
        RECT 0.860 1820.820 1878.430 1821.980 ;
        RECT 0.560 1817.500 1878.430 1820.820 ;
        RECT 0.560 1816.340 1877.710 1817.500 ;
        RECT 0.560 1808.540 1878.430 1816.340 ;
        RECT 0.860 1807.380 1878.430 1808.540 ;
        RECT 0.560 1799.580 1878.430 1807.380 ;
        RECT 0.560 1798.420 1877.710 1799.580 ;
        RECT 0.560 1795.100 1878.430 1798.420 ;
        RECT 0.860 1793.940 1878.430 1795.100 ;
        RECT 0.560 1781.660 1878.430 1793.940 ;
        RECT 0.860 1780.500 1877.710 1781.660 ;
        RECT 0.560 1768.220 1878.430 1780.500 ;
        RECT 0.860 1767.060 1878.430 1768.220 ;
        RECT 0.560 1763.740 1878.430 1767.060 ;
        RECT 0.560 1762.580 1877.710 1763.740 ;
        RECT 0.560 1754.780 1878.430 1762.580 ;
        RECT 0.860 1753.620 1878.430 1754.780 ;
        RECT 0.560 1745.820 1878.430 1753.620 ;
        RECT 0.560 1744.660 1877.710 1745.820 ;
        RECT 0.560 1741.340 1878.430 1744.660 ;
        RECT 0.860 1740.180 1878.430 1741.340 ;
        RECT 0.560 1727.900 1878.430 1740.180 ;
        RECT 0.860 1726.740 1877.710 1727.900 ;
        RECT 0.560 1714.460 1878.430 1726.740 ;
        RECT 0.860 1713.300 1878.430 1714.460 ;
        RECT 0.560 1709.980 1878.430 1713.300 ;
        RECT 0.560 1708.820 1877.710 1709.980 ;
        RECT 0.560 1701.020 1878.430 1708.820 ;
        RECT 0.860 1699.860 1878.430 1701.020 ;
        RECT 0.560 1692.060 1878.430 1699.860 ;
        RECT 0.560 1690.900 1877.710 1692.060 ;
        RECT 0.560 1687.580 1878.430 1690.900 ;
        RECT 0.860 1686.420 1878.430 1687.580 ;
        RECT 0.560 1674.140 1878.430 1686.420 ;
        RECT 0.860 1672.980 1877.710 1674.140 ;
        RECT 0.560 1660.700 1878.430 1672.980 ;
        RECT 0.860 1659.540 1878.430 1660.700 ;
        RECT 0.560 1656.220 1878.430 1659.540 ;
        RECT 0.560 1655.060 1877.710 1656.220 ;
        RECT 0.560 1647.260 1878.430 1655.060 ;
        RECT 0.860 1646.100 1878.430 1647.260 ;
        RECT 0.560 1638.300 1878.430 1646.100 ;
        RECT 0.560 1637.140 1877.710 1638.300 ;
        RECT 0.560 1633.820 1878.430 1637.140 ;
        RECT 0.860 1632.660 1878.430 1633.820 ;
        RECT 0.560 1620.380 1878.430 1632.660 ;
        RECT 0.860 1619.220 1877.710 1620.380 ;
        RECT 0.560 1606.940 1878.430 1619.220 ;
        RECT 0.860 1605.780 1878.430 1606.940 ;
        RECT 0.560 1602.460 1878.430 1605.780 ;
        RECT 0.560 1601.300 1877.710 1602.460 ;
        RECT 0.560 1593.500 1878.430 1601.300 ;
        RECT 0.860 1592.340 1878.430 1593.500 ;
        RECT 0.560 1584.540 1878.430 1592.340 ;
        RECT 0.560 1583.380 1877.710 1584.540 ;
        RECT 0.560 1580.060 1878.430 1583.380 ;
        RECT 0.860 1578.900 1878.430 1580.060 ;
        RECT 0.560 1566.620 1878.430 1578.900 ;
        RECT 0.860 1565.460 1877.710 1566.620 ;
        RECT 0.560 1553.180 1878.430 1565.460 ;
        RECT 0.860 1552.020 1878.430 1553.180 ;
        RECT 0.560 1548.700 1878.430 1552.020 ;
        RECT 0.560 1547.540 1877.710 1548.700 ;
        RECT 0.560 1539.740 1878.430 1547.540 ;
        RECT 0.860 1538.580 1878.430 1539.740 ;
        RECT 0.560 1530.780 1878.430 1538.580 ;
        RECT 0.560 1529.620 1877.710 1530.780 ;
        RECT 0.560 1526.300 1878.430 1529.620 ;
        RECT 0.860 1525.140 1878.430 1526.300 ;
        RECT 0.560 1512.860 1878.430 1525.140 ;
        RECT 0.860 1511.700 1877.710 1512.860 ;
        RECT 0.560 1499.420 1878.430 1511.700 ;
        RECT 0.860 1498.260 1878.430 1499.420 ;
        RECT 0.560 1494.940 1878.430 1498.260 ;
        RECT 0.560 1493.780 1877.710 1494.940 ;
        RECT 0.560 1485.980 1878.430 1493.780 ;
        RECT 0.860 1484.820 1878.430 1485.980 ;
        RECT 0.560 1477.020 1878.430 1484.820 ;
        RECT 0.560 1475.860 1877.710 1477.020 ;
        RECT 0.560 1472.540 1878.430 1475.860 ;
        RECT 0.860 1471.380 1878.430 1472.540 ;
        RECT 0.560 1459.100 1878.430 1471.380 ;
        RECT 0.860 1457.940 1877.710 1459.100 ;
        RECT 0.560 1445.660 1878.430 1457.940 ;
        RECT 0.860 1444.500 1878.430 1445.660 ;
        RECT 0.560 1441.180 1878.430 1444.500 ;
        RECT 0.560 1440.020 1877.710 1441.180 ;
        RECT 0.560 1432.220 1878.430 1440.020 ;
        RECT 0.860 1431.060 1878.430 1432.220 ;
        RECT 0.560 1423.260 1878.430 1431.060 ;
        RECT 0.560 1422.100 1877.710 1423.260 ;
        RECT 0.560 1418.780 1878.430 1422.100 ;
        RECT 0.860 1417.620 1878.430 1418.780 ;
        RECT 0.560 1405.340 1878.430 1417.620 ;
        RECT 0.860 1404.180 1877.710 1405.340 ;
        RECT 0.560 1391.900 1878.430 1404.180 ;
        RECT 0.860 1390.740 1878.430 1391.900 ;
        RECT 0.560 1387.420 1878.430 1390.740 ;
        RECT 0.560 1386.260 1877.710 1387.420 ;
        RECT 0.560 1378.460 1878.430 1386.260 ;
        RECT 0.860 1377.300 1878.430 1378.460 ;
        RECT 0.560 1369.500 1878.430 1377.300 ;
        RECT 0.560 1368.340 1877.710 1369.500 ;
        RECT 0.560 1365.020 1878.430 1368.340 ;
        RECT 0.860 1363.860 1878.430 1365.020 ;
        RECT 0.560 1351.580 1878.430 1363.860 ;
        RECT 0.860 1350.420 1877.710 1351.580 ;
        RECT 0.560 1338.140 1878.430 1350.420 ;
        RECT 0.860 1336.980 1878.430 1338.140 ;
        RECT 0.560 1333.660 1878.430 1336.980 ;
        RECT 0.560 1332.500 1877.710 1333.660 ;
        RECT 0.560 1324.700 1878.430 1332.500 ;
        RECT 0.860 1323.540 1878.430 1324.700 ;
        RECT 0.560 1315.740 1878.430 1323.540 ;
        RECT 0.560 1314.580 1877.710 1315.740 ;
        RECT 0.560 1311.260 1878.430 1314.580 ;
        RECT 0.860 1310.100 1878.430 1311.260 ;
        RECT 0.560 1297.820 1878.430 1310.100 ;
        RECT 0.860 1296.660 1877.710 1297.820 ;
        RECT 0.560 1284.380 1878.430 1296.660 ;
        RECT 0.860 1283.220 1878.430 1284.380 ;
        RECT 0.560 1279.900 1878.430 1283.220 ;
        RECT 0.560 1278.740 1877.710 1279.900 ;
        RECT 0.560 1270.940 1878.430 1278.740 ;
        RECT 0.860 1269.780 1878.430 1270.940 ;
        RECT 0.560 1261.980 1878.430 1269.780 ;
        RECT 0.560 1260.820 1877.710 1261.980 ;
        RECT 0.560 1257.500 1878.430 1260.820 ;
        RECT 0.860 1256.340 1878.430 1257.500 ;
        RECT 0.560 1244.060 1878.430 1256.340 ;
        RECT 0.860 1242.900 1877.710 1244.060 ;
        RECT 0.560 1230.620 1878.430 1242.900 ;
        RECT 0.860 1229.460 1878.430 1230.620 ;
        RECT 0.560 1226.140 1878.430 1229.460 ;
        RECT 0.560 1224.980 1877.710 1226.140 ;
        RECT 0.560 1217.180 1878.430 1224.980 ;
        RECT 0.860 1216.020 1878.430 1217.180 ;
        RECT 0.560 1208.220 1878.430 1216.020 ;
        RECT 0.560 1207.060 1877.710 1208.220 ;
        RECT 0.560 1203.740 1878.430 1207.060 ;
        RECT 0.860 1202.580 1878.430 1203.740 ;
        RECT 0.560 1190.300 1878.430 1202.580 ;
        RECT 0.860 1189.140 1877.710 1190.300 ;
        RECT 0.560 1176.860 1878.430 1189.140 ;
        RECT 0.860 1175.700 1878.430 1176.860 ;
        RECT 0.560 1172.380 1878.430 1175.700 ;
        RECT 0.560 1171.220 1877.710 1172.380 ;
        RECT 0.560 1163.420 1878.430 1171.220 ;
        RECT 0.860 1162.260 1878.430 1163.420 ;
        RECT 0.560 1154.460 1878.430 1162.260 ;
        RECT 0.560 1153.300 1877.710 1154.460 ;
        RECT 0.560 1149.980 1878.430 1153.300 ;
        RECT 0.860 1148.820 1878.430 1149.980 ;
        RECT 0.560 1136.540 1878.430 1148.820 ;
        RECT 0.860 1135.380 1877.710 1136.540 ;
        RECT 0.560 1123.100 1878.430 1135.380 ;
        RECT 0.860 1121.940 1878.430 1123.100 ;
        RECT 0.560 1118.620 1878.430 1121.940 ;
        RECT 0.560 1117.460 1877.710 1118.620 ;
        RECT 0.560 1109.660 1878.430 1117.460 ;
        RECT 0.860 1108.500 1878.430 1109.660 ;
        RECT 0.560 1100.700 1878.430 1108.500 ;
        RECT 0.560 1099.540 1877.710 1100.700 ;
        RECT 0.560 1096.220 1878.430 1099.540 ;
        RECT 0.860 1095.060 1878.430 1096.220 ;
        RECT 0.560 1082.780 1878.430 1095.060 ;
        RECT 0.860 1081.620 1877.710 1082.780 ;
        RECT 0.560 1069.340 1878.430 1081.620 ;
        RECT 0.860 1068.180 1878.430 1069.340 ;
        RECT 0.560 1064.860 1878.430 1068.180 ;
        RECT 0.560 1063.700 1877.710 1064.860 ;
        RECT 0.560 1055.900 1878.430 1063.700 ;
        RECT 0.860 1054.740 1878.430 1055.900 ;
        RECT 0.560 1046.940 1878.430 1054.740 ;
        RECT 0.560 1045.780 1877.710 1046.940 ;
        RECT 0.560 1042.460 1878.430 1045.780 ;
        RECT 0.860 1041.300 1878.430 1042.460 ;
        RECT 0.560 1029.020 1878.430 1041.300 ;
        RECT 0.860 1027.860 1877.710 1029.020 ;
        RECT 0.560 1015.580 1878.430 1027.860 ;
        RECT 0.860 1014.420 1878.430 1015.580 ;
        RECT 0.560 1011.100 1878.430 1014.420 ;
        RECT 0.560 1009.940 1877.710 1011.100 ;
        RECT 0.560 1002.140 1878.430 1009.940 ;
        RECT 0.860 1000.980 1878.430 1002.140 ;
        RECT 0.560 993.180 1878.430 1000.980 ;
        RECT 0.560 992.020 1877.710 993.180 ;
        RECT 0.560 988.700 1878.430 992.020 ;
        RECT 0.860 987.540 1878.430 988.700 ;
        RECT 0.560 975.260 1878.430 987.540 ;
        RECT 0.860 974.100 1877.710 975.260 ;
        RECT 0.560 961.820 1878.430 974.100 ;
        RECT 0.860 960.660 1878.430 961.820 ;
        RECT 0.560 957.340 1878.430 960.660 ;
        RECT 0.560 956.180 1877.710 957.340 ;
        RECT 0.560 948.380 1878.430 956.180 ;
        RECT 0.860 947.220 1878.430 948.380 ;
        RECT 0.560 939.420 1878.430 947.220 ;
        RECT 0.560 938.260 1877.710 939.420 ;
        RECT 0.560 934.940 1878.430 938.260 ;
        RECT 0.860 933.780 1878.430 934.940 ;
        RECT 0.560 921.500 1878.430 933.780 ;
        RECT 0.860 920.340 1877.710 921.500 ;
        RECT 0.560 908.060 1878.430 920.340 ;
        RECT 0.860 906.900 1878.430 908.060 ;
        RECT 0.560 903.580 1878.430 906.900 ;
        RECT 0.560 902.420 1877.710 903.580 ;
        RECT 0.560 894.620 1878.430 902.420 ;
        RECT 0.860 893.460 1878.430 894.620 ;
        RECT 0.560 885.660 1878.430 893.460 ;
        RECT 0.560 884.500 1877.710 885.660 ;
        RECT 0.560 881.180 1878.430 884.500 ;
        RECT 0.860 880.020 1878.430 881.180 ;
        RECT 0.560 867.740 1878.430 880.020 ;
        RECT 0.860 866.580 1877.710 867.740 ;
        RECT 0.560 854.300 1878.430 866.580 ;
        RECT 0.860 853.140 1878.430 854.300 ;
        RECT 0.560 849.820 1878.430 853.140 ;
        RECT 0.560 848.660 1877.710 849.820 ;
        RECT 0.560 840.860 1878.430 848.660 ;
        RECT 0.860 839.700 1878.430 840.860 ;
        RECT 0.560 831.900 1878.430 839.700 ;
        RECT 0.560 830.740 1877.710 831.900 ;
        RECT 0.560 827.420 1878.430 830.740 ;
        RECT 0.860 826.260 1878.430 827.420 ;
        RECT 0.560 813.980 1878.430 826.260 ;
        RECT 0.860 812.820 1877.710 813.980 ;
        RECT 0.560 800.540 1878.430 812.820 ;
        RECT 0.860 799.380 1878.430 800.540 ;
        RECT 0.560 796.060 1878.430 799.380 ;
        RECT 0.560 794.900 1877.710 796.060 ;
        RECT 0.560 787.100 1878.430 794.900 ;
        RECT 0.860 785.940 1878.430 787.100 ;
        RECT 0.560 778.140 1878.430 785.940 ;
        RECT 0.560 776.980 1877.710 778.140 ;
        RECT 0.560 773.660 1878.430 776.980 ;
        RECT 0.860 772.500 1878.430 773.660 ;
        RECT 0.560 760.220 1878.430 772.500 ;
        RECT 0.860 759.060 1877.710 760.220 ;
        RECT 0.560 746.780 1878.430 759.060 ;
        RECT 0.860 745.620 1878.430 746.780 ;
        RECT 0.560 742.300 1878.430 745.620 ;
        RECT 0.560 741.140 1877.710 742.300 ;
        RECT 0.560 733.340 1878.430 741.140 ;
        RECT 0.860 732.180 1878.430 733.340 ;
        RECT 0.560 724.380 1878.430 732.180 ;
        RECT 0.560 723.220 1877.710 724.380 ;
        RECT 0.560 719.900 1878.430 723.220 ;
        RECT 0.860 718.740 1878.430 719.900 ;
        RECT 0.560 706.460 1878.430 718.740 ;
        RECT 0.860 705.300 1877.710 706.460 ;
        RECT 0.560 693.020 1878.430 705.300 ;
        RECT 0.860 691.860 1878.430 693.020 ;
        RECT 0.560 688.540 1878.430 691.860 ;
        RECT 0.560 687.380 1877.710 688.540 ;
        RECT 0.560 679.580 1878.430 687.380 ;
        RECT 0.860 678.420 1878.430 679.580 ;
        RECT 0.560 670.620 1878.430 678.420 ;
        RECT 0.560 669.460 1877.710 670.620 ;
        RECT 0.560 666.140 1878.430 669.460 ;
        RECT 0.860 664.980 1878.430 666.140 ;
        RECT 0.560 652.700 1878.430 664.980 ;
        RECT 0.860 651.540 1877.710 652.700 ;
        RECT 0.560 639.260 1878.430 651.540 ;
        RECT 0.860 638.100 1878.430 639.260 ;
        RECT 0.560 634.780 1878.430 638.100 ;
        RECT 0.560 633.620 1877.710 634.780 ;
        RECT 0.560 625.820 1878.430 633.620 ;
        RECT 0.860 624.660 1878.430 625.820 ;
        RECT 0.560 616.860 1878.430 624.660 ;
        RECT 0.560 615.700 1877.710 616.860 ;
        RECT 0.560 612.380 1878.430 615.700 ;
        RECT 0.860 611.220 1878.430 612.380 ;
        RECT 0.560 598.940 1878.430 611.220 ;
        RECT 0.860 597.780 1877.710 598.940 ;
        RECT 0.560 585.500 1878.430 597.780 ;
        RECT 0.860 584.340 1878.430 585.500 ;
        RECT 0.560 581.020 1878.430 584.340 ;
        RECT 0.560 579.860 1877.710 581.020 ;
        RECT 0.560 572.060 1878.430 579.860 ;
        RECT 0.860 570.900 1878.430 572.060 ;
        RECT 0.560 563.100 1878.430 570.900 ;
        RECT 0.560 561.940 1877.710 563.100 ;
        RECT 0.560 558.620 1878.430 561.940 ;
        RECT 0.860 557.460 1878.430 558.620 ;
        RECT 0.560 545.180 1878.430 557.460 ;
        RECT 0.860 544.020 1877.710 545.180 ;
        RECT 0.560 531.740 1878.430 544.020 ;
        RECT 0.860 530.580 1878.430 531.740 ;
        RECT 0.560 527.260 1878.430 530.580 ;
        RECT 0.560 526.100 1877.710 527.260 ;
        RECT 0.560 518.300 1878.430 526.100 ;
        RECT 0.860 517.140 1878.430 518.300 ;
        RECT 0.560 509.340 1878.430 517.140 ;
        RECT 0.560 508.180 1877.710 509.340 ;
        RECT 0.560 504.860 1878.430 508.180 ;
        RECT 0.860 503.700 1878.430 504.860 ;
        RECT 0.560 491.420 1878.430 503.700 ;
        RECT 0.860 490.260 1877.710 491.420 ;
        RECT 0.560 477.980 1878.430 490.260 ;
        RECT 0.860 476.820 1878.430 477.980 ;
        RECT 0.560 473.500 1878.430 476.820 ;
        RECT 0.560 472.340 1877.710 473.500 ;
        RECT 0.560 464.540 1878.430 472.340 ;
        RECT 0.860 463.380 1878.430 464.540 ;
        RECT 0.560 455.580 1878.430 463.380 ;
        RECT 0.560 454.420 1877.710 455.580 ;
        RECT 0.560 451.100 1878.430 454.420 ;
        RECT 0.860 449.940 1878.430 451.100 ;
        RECT 0.560 437.660 1878.430 449.940 ;
        RECT 0.860 436.500 1877.710 437.660 ;
        RECT 0.560 424.220 1878.430 436.500 ;
        RECT 0.860 423.060 1878.430 424.220 ;
        RECT 0.560 419.740 1878.430 423.060 ;
        RECT 0.560 418.580 1877.710 419.740 ;
        RECT 0.560 410.780 1878.430 418.580 ;
        RECT 0.860 409.620 1878.430 410.780 ;
        RECT 0.560 401.820 1878.430 409.620 ;
        RECT 0.560 400.660 1877.710 401.820 ;
        RECT 0.560 397.340 1878.430 400.660 ;
        RECT 0.860 396.180 1878.430 397.340 ;
        RECT 0.560 383.900 1878.430 396.180 ;
        RECT 0.860 382.740 1877.710 383.900 ;
        RECT 0.560 370.460 1878.430 382.740 ;
        RECT 0.860 369.300 1878.430 370.460 ;
        RECT 0.560 365.980 1878.430 369.300 ;
        RECT 0.560 364.820 1877.710 365.980 ;
        RECT 0.560 357.020 1878.430 364.820 ;
        RECT 0.860 355.860 1878.430 357.020 ;
        RECT 0.560 348.060 1878.430 355.860 ;
        RECT 0.560 346.900 1877.710 348.060 ;
        RECT 0.560 343.580 1878.430 346.900 ;
        RECT 0.860 342.420 1878.430 343.580 ;
        RECT 0.560 330.140 1878.430 342.420 ;
        RECT 0.860 328.980 1877.710 330.140 ;
        RECT 0.560 316.700 1878.430 328.980 ;
        RECT 0.860 315.540 1878.430 316.700 ;
        RECT 0.560 312.220 1878.430 315.540 ;
        RECT 0.560 311.060 1877.710 312.220 ;
        RECT 0.560 303.260 1878.430 311.060 ;
        RECT 0.860 302.100 1878.430 303.260 ;
        RECT 0.560 294.300 1878.430 302.100 ;
        RECT 0.560 293.140 1877.710 294.300 ;
        RECT 0.560 289.820 1878.430 293.140 ;
        RECT 0.860 288.660 1878.430 289.820 ;
        RECT 0.560 276.380 1878.430 288.660 ;
        RECT 0.860 275.220 1877.710 276.380 ;
        RECT 0.560 262.940 1878.430 275.220 ;
        RECT 0.860 261.780 1878.430 262.940 ;
        RECT 0.560 258.460 1878.430 261.780 ;
        RECT 0.560 257.300 1877.710 258.460 ;
        RECT 0.560 249.500 1878.430 257.300 ;
        RECT 0.860 248.340 1878.430 249.500 ;
        RECT 0.560 240.540 1878.430 248.340 ;
        RECT 0.560 239.380 1877.710 240.540 ;
        RECT 0.560 236.060 1878.430 239.380 ;
        RECT 0.860 234.900 1878.430 236.060 ;
        RECT 0.560 222.620 1878.430 234.900 ;
        RECT 0.860 221.460 1877.710 222.620 ;
        RECT 0.560 209.180 1878.430 221.460 ;
        RECT 0.860 208.020 1878.430 209.180 ;
        RECT 0.560 204.700 1878.430 208.020 ;
        RECT 0.560 203.540 1877.710 204.700 ;
        RECT 0.560 195.740 1878.430 203.540 ;
        RECT 0.860 194.580 1878.430 195.740 ;
        RECT 0.560 186.780 1878.430 194.580 ;
        RECT 0.560 185.620 1877.710 186.780 ;
        RECT 0.560 182.300 1878.430 185.620 ;
        RECT 0.860 181.140 1878.430 182.300 ;
        RECT 0.560 168.860 1878.430 181.140 ;
        RECT 0.860 167.700 1877.710 168.860 ;
        RECT 0.560 155.420 1878.430 167.700 ;
        RECT 0.860 154.260 1878.430 155.420 ;
        RECT 0.560 150.940 1878.430 154.260 ;
        RECT 0.560 149.780 1877.710 150.940 ;
        RECT 0.560 141.980 1878.430 149.780 ;
        RECT 0.860 140.820 1878.430 141.980 ;
        RECT 0.560 133.020 1878.430 140.820 ;
        RECT 0.560 131.860 1877.710 133.020 ;
        RECT 0.560 128.540 1878.430 131.860 ;
        RECT 0.860 127.380 1878.430 128.540 ;
        RECT 0.560 115.100 1878.430 127.380 ;
        RECT 0.860 113.940 1877.710 115.100 ;
        RECT 0.560 101.660 1878.430 113.940 ;
        RECT 0.860 100.500 1878.430 101.660 ;
        RECT 0.560 97.180 1878.430 100.500 ;
        RECT 0.560 96.020 1877.710 97.180 ;
        RECT 0.560 88.220 1878.430 96.020 ;
        RECT 0.860 87.060 1878.430 88.220 ;
        RECT 0.560 79.260 1878.430 87.060 ;
        RECT 0.560 78.100 1877.710 79.260 ;
        RECT 0.560 74.780 1878.430 78.100 ;
        RECT 0.860 73.620 1878.430 74.780 ;
        RECT 0.560 61.340 1878.430 73.620 ;
        RECT 0.860 60.180 1877.710 61.340 ;
        RECT 0.560 47.900 1878.430 60.180 ;
        RECT 0.860 46.740 1878.430 47.900 ;
        RECT 0.560 43.420 1878.430 46.740 ;
        RECT 0.560 42.260 1877.710 43.420 ;
        RECT 0.560 0.140 1878.430 42.260 ;
      LAYER Metal4 ;
        RECT 7.980 31.450 21.940 1850.710 ;
        RECT 24.140 31.450 25.240 1850.710 ;
        RECT 27.440 31.450 175.540 1850.710 ;
        RECT 177.740 31.450 178.840 1850.710 ;
        RECT 181.040 31.450 329.140 1850.710 ;
        RECT 331.340 31.450 332.440 1850.710 ;
        RECT 334.640 31.450 482.740 1850.710 ;
        RECT 484.940 31.450 486.040 1850.710 ;
        RECT 488.240 31.450 636.340 1850.710 ;
        RECT 638.540 31.450 639.640 1850.710 ;
        RECT 641.840 31.450 789.940 1850.710 ;
        RECT 792.140 31.450 793.240 1850.710 ;
        RECT 795.440 31.450 943.540 1850.710 ;
        RECT 945.740 31.450 946.840 1850.710 ;
        RECT 949.040 31.450 1097.140 1850.710 ;
        RECT 1099.340 31.450 1100.440 1850.710 ;
        RECT 1102.640 31.450 1250.740 1850.710 ;
        RECT 1252.940 31.450 1254.040 1850.710 ;
        RECT 1256.240 31.450 1404.340 1850.710 ;
        RECT 1406.540 31.450 1407.640 1850.710 ;
        RECT 1409.840 31.450 1557.940 1850.710 ;
        RECT 1560.140 31.450 1561.240 1850.710 ;
        RECT 1563.440 31.450 1711.540 1850.710 ;
        RECT 1713.740 31.450 1714.840 1850.710 ;
        RECT 1717.040 31.450 1865.140 1850.710 ;
        RECT 1867.340 31.450 1868.440 1850.710 ;
        RECT 1870.640 31.450 1878.100 1850.710 ;
  END
END az_v_core_top
END LIBRARY

